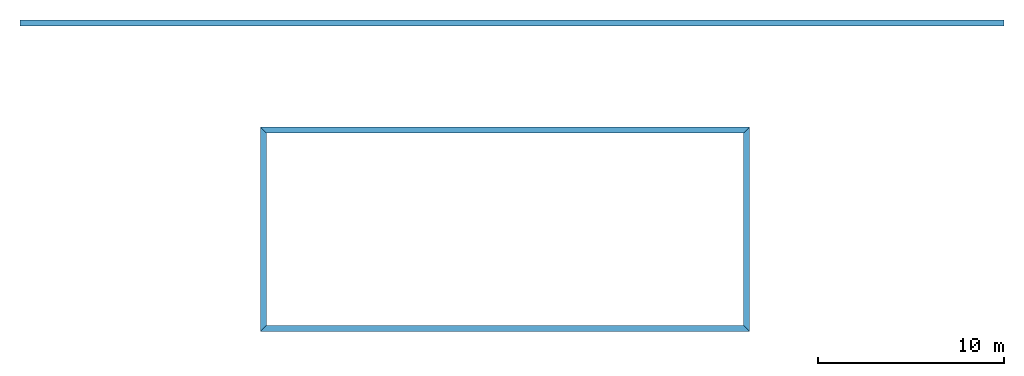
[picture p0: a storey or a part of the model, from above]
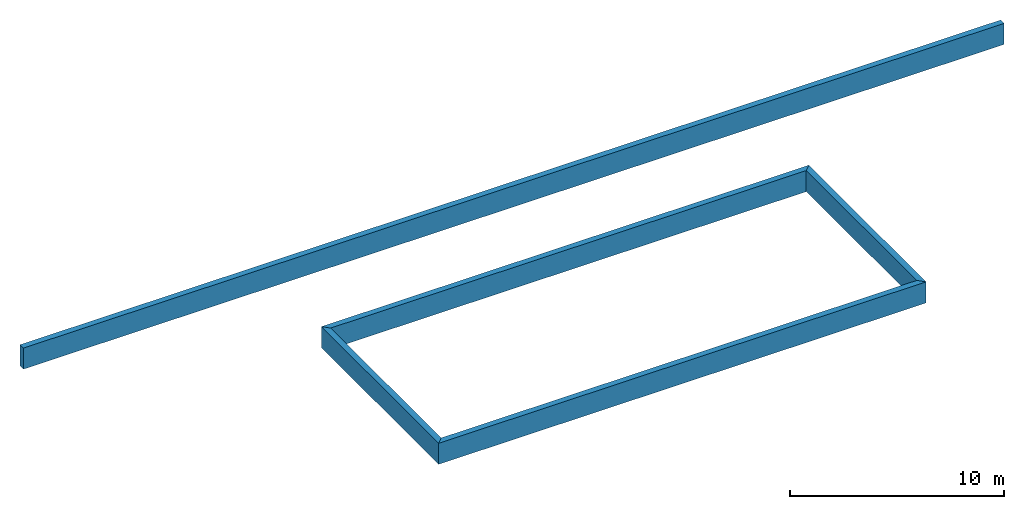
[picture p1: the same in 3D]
Properties of the parts of a building model (IFC2X3), part 1 of 2

# File
Description: ViewDefinition [CoordinationView_V2.0], Option [Elements to export: Visible elements (on all stories)], Option [Partial Structure Display: Entire Model], Option [IFC Domain: All], Option [Structural Function: All Elements], Option [Convert Grid elements: On], Option [Convert IFC Annotations and Archicad 2D elements: Off], Option [Convert 2D symbols of Doors and Windows: Off], Option [Export geometries that Participates in Collision Detection only: Off], Option [Split complex elements: Off], Option [Material Preservation: Explode where necessary], Option [Elements in Solid Element Operations: Extruded/revolved], Option [Elements with junctions: Extruded/revolved without junctions], Option [IFC Model position: Survey Point and Project Origin], Option [Curtain Wall export mode: Container Element], Option [Railing export mode: Single Element], Option [Stair export mode: Container Element], Option [Properties To Export: All properties], Option [Space containment: Off], Option [Geometry to type objects: Off], Option [Element Properties: All], Option [Building Material Properties: Off], Option [Element Parameters: Off], Option [Component Parameters: Off], Option [IFC Base Quantities: Off], Option [Door Window Parameters: On], Option [IFC Space boundaries: Off], Option [Archicad Zone Categories as IFC Space classification data: Off], Option [Element Classifications: On]
File name: \\Mac\Dropbox\PROJECTES\PROJECTES ACTIUS\1791- CR-BQ FA3\ENTREGUES\CR_BLOC FASE 3_01_05\EDITABLES\DOC GRÀFICA\CR-BLOC FASE 3_v4.ifc
Time: 2026-05-06T10:31:25
Author: Architect
Organization: Building Designer Office
Written by: DDS_IFC v3.0
Made in: Graphisoft - Archicad - 29.0.0
Authorization: The authorising person

# IfcSite, Sitio
RefLatitude: 47, 33, 34, 948800; RefLongitude: 19, 3, 17, 204400; RefElevation: 0 mm

# IfcBuildingStorey (4)
In: Construcción
Name | Elevation (mm)
PLANTA 3 | 7300
PLANTA 1ª | 0
PLANTA 2ª | 3650
-1. Piso | -3650

# IfcBuildingElementProxy: ARQ_GN002_Generic Estructural 250 x 345 (6)
Material: ARQ_GN002_Generic Estructural
AC_Pset_RenovationAndPhasing - Renovation Status: Existing
Name | In
2 x CRE - 005 | -1. Piso
2 x CRE - 005 | PLANTA 1ª
2 x CRE - 005 | PLANTA 2ª

# IfcBuildingElementProxy: ARQ_GN002_Generic Estructural 350 x 299 (3)
Material: ARQ_GN002_Generic Estructural
AC_Pset_RenovationAndPhasing - Renovation Status: Existing
Name | In
CRE - 005 | -1. Piso
CRE - 005 | PLANTA 1ª
CRE - 005 | PLANTA 2ª

# IfcBuildingElementProxy: ARQ_GN002_Generic Estructural 350 x 360 (3)
Material: ARQ_GN002_Generic Estructural
AC_Pset_RenovationAndPhasing - Renovation Status: Existing
Name | In
CRE - 005 | -1. Piso
CRE - 005 | PLANTA 1ª
CRE - 005 | PLANTA 2ª

# IfcBuildingElementProxy: ARQ_GN002_Generic Estructural 350 x 400 (3)
Material: ARQ_GN002_Generic Estructural
AC_Pset_RenovationAndPhasing - Renovation Status: Existing
Name | In
CRE - 005 | -1. Piso
CRE - 005 | PLANTA 1ª
CRE - 005 | PLANTA 2ª

# IfcBuildingElementProxy: ARQ_GN002_Generic Estructural 350 x 445 (2)
Material: ARQ_GN002_Generic Estructural
AC_Pset_RenovationAndPhasing - Renovation Status: Existing
Name | In
CRE - 005 | -1. Piso
CRE - 005 | PLANTA 1ª

# IfcBuildingElementProxy: ARQ_GN002_Generic Estructural 350 x 450 (39)
Material: ARQ_GN002_Generic Estructural
AC_Pset_RenovationAndPhasing - Renovation Status: Existing
Name | In
14 x CRE - 005 | -1. Piso
13 x CRE - 005 | PLANTA 1ª
12 x CRE - 005 | PLANTA 2ª

# IfcBuildingElementProxy: ARQ_GN002_Generic Estructural 350 x 515 (2)
In: PLANTA 2ª
Material: ARQ_GN002_Generic Estructural
AC_Pset_RenovationAndPhasing - Renovation Status: Existing

# IfcBuildingElementProxy: ARQ_GN002_Generic Estructural 350 x 605, CRE - 005
In: PLANTA 2ª
Material: ARQ_GN002_Generic Estructural
AC_Pset_RenovationAndPhasing - Renovation Status: Existing

# IfcBuildingElementProxy: ARQ_GN002_Generic Estructural 353 x 445 (3)
Material: ARQ_GN002_Generic Estructural
AC_Pset_RenovationAndPhasing - Renovation Status: Existing
Name | In
CRE - 005 | -1. Piso
CRE - 005 | PLANTA 1ª
CRE - 005 | PLANTA 2ª

# IfcBuildingElementProxy: ARQ_GN002_Generic Estructural 353 x 450 (3)
Material: ARQ_GN002_Generic Estructural
AC_Pset_RenovationAndPhasing - Renovation Status: Existing
Name | In
CRE - 005 | -1. Piso
CRE - 005 | PLANTA 1ª
CRE - 005 | PLANTA 2ª

# IfcBuildingElementProxy: ARQ_GN002_Generic Estructural 353 x 451, CRE - 005
In: PLANTA 2ª
Material: ARQ_GN002_Generic Estructural
AC_Pset_RenovationAndPhasing - Renovation Status: Existing

# IfcBuildingElementProxy: ARQ_GN002_Generic Estructural 400 x 400 (20)
Material: ARQ_GN002_Generic Estructural
AC_Pset_RenovationAndPhasing - Renovation Status: Existing
Name | In
7 x CRE - 005 | -1. Piso
8 x CRE - 005 | PLANTA 1ª
5 x CRE - 005 | PLANTA 2ª

# IfcBuildingElementProxy: ARQ_GN002_Generic Estructural 400 x 405 (28)
Material: ARQ_GN002_Generic Estructural
AC_Pset_RenovationAndPhasing - Renovation Status: Existing
Name | In
8 x CRE - 005 | -1. Piso
7 x CRE - 005 | PLANTA 1ª
13 x CRE - 005 | PLANTA 2ª

# IfcBuildingElementProxy: ARQ_GN002_Generic Estructural 400 x 552, CRE - 005
In: PLANTA 2ª
Material: ARQ_GN002_Generic Estructural
AC_Pset_RenovationAndPhasing - Renovation Status: Existing

# IfcBuildingElementProxy: ARQ_GN002_Generic Estructural 400 x 555, CRE - 005
In: PLANTA 2ª
Material: ARQ_GN002_Generic Estructural
AC_Pset_RenovationAndPhasing - Renovation Status: Existing

# IfcBuildingElementProxy: ARQ_GN002_Generic Estructural 410 x 400 (3)
Material: ARQ_GN002_Generic Estructural
AC_Pset_RenovationAndPhasing - Renovation Status: Existing
Name | In
CRE - 005 | -1. Piso
CRE - 005 | PLANTA 1ª
CRE - 005 | PLANTA 2ª

# IfcBuildingElementProxy: ARQ_GN002_Generic Estructural 451 x 320 (3)
Material: ARQ_GN002_Generic Estructural
AC_Pset_RenovationAndPhasing - Renovation Status: Existing
Name | In
CRE - 005 | -1. Piso
CRE - 005 | PLANTA 1ª
CRE - 005 | PLANTA 2ª

# IfcBuildingElementProxy: ARQ_GN002_Generic Estructural 513 x 445 (3)
Material: ARQ_GN002_Generic Estructural
AC_Pset_RenovationAndPhasing - Renovation Status: Existing
Name | In
CRE - 005 | -1. Piso
CRE - 005 | PLANTA 1ª
CRE - 005 | PLANTA 2ª

# IfcBuildingElementProxy: ARQ_GN002_Generic Estructural 562 x 445 (2)
Material: ARQ_GN002_Generic Estructural
AC_Pset_RenovationAndPhasing - Renovation Status: Existing
Name | In
CRE - 005 | -1. Piso
CRE - 005 | PLANTA 1ª

# IfcBuildingElementProxy: ARQ_GN002_Generic Estructural 562 x 605, CRE - 005
In: PLANTA 2ª
Material: ARQ_GN002_Generic Estructural
AC_Pset_RenovationAndPhasing - Renovation Status: Existing

# IfcBuildingElementProxy: Puerta 27 (28)
Name | In | Renovation Status
PF-07D | PLANTA 1ª | Existing
PF-08D | PLANTA 1ª | Existing
PF-04D | PLANTA 1ª | Existing
PF-05D | PLANTA 1ª | Existing
PF-06D | PLANTA 1ª | Existing
PF-10D | PLANTA 1ª | Existing
PF-09D | PLANTA 1ª | Existing
3 x P-02 | PLANTA 1ª | New
P-03 | PLANTA 1ª | New
PM-3 | PLANTA 1ª | New
PF-04D | PLANTA 2ª | Existing
2 x PF-05D | PLANTA 2ª | Existing
PF-06D | PLANTA 2ª | Existing
PF-19D | PLANTA 2ª | Existing
PF-23D | PLANTA 2ª | Existing
PF-26D | PLANTA 2ª | Existing
PF-25D | PLANTA 2ª | Existing
PF-20D | PLANTA 2ª | Existing
PF-22D | PLANTA 2ª | Existing
PF-24D | PLANTA 2ª | Existing
PF-21D | PLANTA 2ª | Existing
PF-18D | PLANTA 2ª | Existing
P-03 | PLANTA 2ª | New
P-02 | PLANTA 2ª | New
PM-3 | PLANTA 2ª | New

# IfcBuildingElementProxy: Puerta Corredera Empotrada 27 (19)
Name | In | Renovation Status
6 x P-01 | PLANTA 1ª | New
3 x P-04 | PLANTA 1ª | New
5 x PF-14D | PLANTA 2ª | Existing
3 x P-04 | PLANTA 2ª | New
2 x P-01 | PLANTA 2ª | New

# IfcBuildingElementProxy: Puerta Corredera Exterior 27 (9)
Name | In | Renovation Status
PF-12D | PLANTA 1ª | Existing
P-05 | PLANTA 1ª | New
PM-2 | PLANTA 1ª | New
5 x PF-13D | PLANTA 2ª | Existing
P-05 | PLANTA 2ª | New

# IfcBuildingElementProxy: Puerta Doble 27 (8)
Name | In | Renovation Status
PM-4 | PLANTA 1ª | New
PF-15D | PLANTA 1ª | Existing
PM-4 | PLANTA 2ª | New
2 x PF-31D | PLANTA 2ª | Existing
2 x PF-32D | PLANTA 2ª | Existing
PF-30D | PLANTA 2ª | Existing

# IfcBuildingElementProxy: Puerta Entrada 27, PM-1
In: PLANTA 1ª
AC_Pset_RenovationAndPhasing - Renovation Status: New

# IfcBuildingElementProxy: Puerta Metal 27 (4)
AC_Pset_RenovationAndPhasing - Renovation Status: New
Name | In
P-02 | PLANTA 1ª
PF-1 | PLANTA 1ª
P-02 | PLANTA 2ª
PF-1 | PLANTA 2ª

# IfcBuildingElementProxy: Puerta Metal Doble 27 (2)
AC_Pset_RenovationAndPhasing - Renovation Status: New
Name | In
PF-2 | PLANTA 1ª
PF-2 | PLANTA 2ª

# IfcBuildingElementProxy: Puerta Rápida Enrrollable 27 (4)
AC_Pset_RenovationAndPhasing - Renovation Status: New
Name | In
2 x P- Transfer | PLANTA 1ª
2 x P- Transfer | PLANTA 2ª

# IfcBuildingElementProxy: Ventana 27 (4)
AC_Pset_RenovationAndPhasing - Renovation Status: New
Name | In
3 x F-02 | PLANTA 1ª
F-02 | PLANTA 2ª

# IfcBuildingElementProxy: Ventana Escaparate 27 (15)
Pset_ManufacturerOccurrence - SerialNumber: No
AC_Pset_RenovationAndPhasing - Renovation Status: New
Name | In
M-08 | PLANTA 1ª
M-09 | PLANTA 1ª
M-02 | PLANTA 1ª
M-01 | PLANTA 1ª
M-06 | PLANTA 1ª
M-07 | PLANTA 1ª
M-04 | PLANTA 1ª
M-03 | PLANTA 1ª
M-11 | PLANTA 1ª
M-05 | PLANTA 1ª
M-13 | PLANTA 2ª
M-14 | PLANTA 2ª
M-15 | PLANTA 2ª
M-12 | PLANTA 2ª
M-10 | PLANTA 1ª

# IfcBuildingElementProxy: Ventana Vertical Multi-Faja 27 (57)
Name | In | Renovation Status
17 x V - 008 | -1. Piso | Existing
12 x F01 | PLANTA 1ª | Existing
5 x V - 008 | PLANTA 1ª | Existing
V - 010 | PLANTA 1ª | Existing
V - 009 | PLANTA 1ª | Existing
F01 | PLANTA 1ª | New
9 x V - 008 | PLANTA 2ª | Existing
V - 013 | PLANTA 2ª | Existing
V - 012 | PLANTA 2ª | Existing
V - 011 | PLANTA 2ª | Existing
8 x F01 | PLANTA 2ª | Existing

# IfcCovering: ARQ_AM253_Tarkett IQ Clar 2 (9)
Classification: 40.20.20.20 Paviments (GuBIMclass CA); Material: ARQ_AM253_Tarkett IQ Clar
06-ESPAIS - 06-05-Superficie: 0 m2; 06-01-Tipus us general: .; 06-01-Tipus us especific: .; 06-02-Numero: 0; 06-03-Nom: .; 06-04-Nivell: .; 06-03-Alçada lliure: 0; 06-06-Ocupació: 0
04-DIMENSIONS - 04-03-Alçada-m: 2 mm; 04-04-Espesor-m: 2 mm; 04-06-Area-m2: 0 m2; 04-07-Volum-m3: 0; 04-08-Diametre-Exterior: 0; 04-09-Diametre-Interior: 0
AC_Pset_RenovationAndPhasing - Renovation Status: New
07-PROPIETATS GENERALS - 07-01-Acabat: HPL
05-MANTENIMENT - 05-01-Fabricant: .; 05-02-Marca: .; 05-03-Model: .; 05-06-Data installacio: aa/mm/dd; 05-07-Data inici garantia: aa/mm/dd; 05-08-Data final garantia: aa/mm/dd
03-PRETACIONS - 03-01-Material: .; 03-02-RF: 0; 03-03-Pes-Kg: 0; 03-04-Potencia-W: 0; 03-05-Voltatge-V: 0; 03-06-Cabal -l/s: 0
02-LOCALIZACIÓ - 02-01-Nivell localització: .; 02-02-Codi ubicacio: .
01-IDENTIFICADOR - 01-04-Tipus installacio: .; 01-05-Unitat de mesura: .
Pset_CoveringCommon - Material: ARQ_AM253_Tarkett IQ Clar; TotalThickness: 2 mm
Name | In | 04-05-Perímetre-m (m2) | 01-01-Nom tipus
SLA - 013 | PLANTA 1ª | 3.22825 | SLA - 013
SLA - 013 | PLANTA 1ª | 223.981 | SLA - 013
SLA - 014 | PLANTA 1ª | 3.20742 | SLA - 014
SLA - 013 | PLANTA 1ª | 26.1483 | SLA - 013
SLA - 013 | PLANTA 1ª | 13.7227 | SLA - 013
SLA - 013 | PLANTA 1ª | 6.23319 | SLA - 013
SLA - 013 | PLANTA 1ª | 3.23513 | SLA - 013
SLA - 013 | PLANTA 2ª | 0.0376921 | SLA - 013
SLA - 013 | PLANTA 2ª | 205.367 | SLA - 013

# IfcCovering: ARQ_AM253_Tarkett IQ Habitacions 2 (4)
Classification: 40.20.20.20 Paviments (GuBIMclass CA); Material: ARQ_AM253_Tarkett IQ Habitacions
Pset_CoveringCommon - Material: ARQ_AM253_Tarkett IQ Habitacions; TotalThickness: 2 mm
01-IDENTIFICADOR - 01-01-Nom tipus: SLA - 013; 01-04-Tipus installacio: .; 01-05-Unitat de mesura: .
02-LOCALIZACIÓ - 02-01-Nivell localització: .; 02-02-Codi ubicacio: .
03-PRETACIONS - 03-01-Material: .; 03-02-RF: 0; 03-03-Pes-Kg: 0; 03-04-Potencia-W: 0; 03-05-Voltatge-V: 0; 03-06-Cabal -l/s: 0
04-DIMENSIONS - 04-07-Volum-m3: 0; 04-08-Diametre-Exterior: 0; 04-09-Diametre-Interior: 0; 04-03-Alçada-m: 2 mm; 04-04-Espesor-m: 2 mm; 04-06-Area-m2: 0 m2
05-MANTENIMENT - 05-01-Fabricant: .; 05-02-Marca: .; 05-03-Model: .; 05-06-Data installacio: aa/mm/dd; 05-07-Data inici garantia: aa/mm/dd; 05-08-Data final garantia: aa/mm/dd
07-PROPIETATS GENERALS - 07-01-Acabat: HPL
AC_Pset_RenovationAndPhasing - Renovation Status: Existing
06-ESPAIS - 06-05-Superficie: 0 m2; 06-01-Tipus us general: .; 06-01-Tipus us especific: .; 06-02-Numero: 0; 06-03-Nom: .; 06-04-Nivell: .; 06-03-Alçada lliure: 0; 06-06-Ocupació: 0
Name | In | 04-05-Perímetre-m (m2)
SLA - 013 | PLANTA 1ª | 70.9887
SLA - 013 | PLANTA 1ª | 74.5234
SLA - 013 | PLANTA 2ª | 61.8411
SLA - 013 | PLANTA 2ª | 65.547

# IfcFurnishingElement: Armario Mural 2P 10 (4)
In: PLANTA 1ª
Classification: 60.20.30.70 Altres mobiliaris mòbils (GuBIMclass CA)
01-IDENTIFICADOR - 01-01-Nom tipus: 60.20.66 Armari; 01-04-Tipus installacio: .; 01-05-Unitat de mesura: .
03-PRETACIONS - 03-01-Material: .; 03-02-RF: 0; 03-03-Pes-Kg: 0; 03-04-Potencia-W: 0; 03-05-Voltatge-V: 0; 03-06-Cabal -l/s: 0
02-LOCALIZACIÓ - 02-01-Nivell localització: .; 02-02-Codi ubicacio: .
04-DIMENSIONS - 04-07-Volum-m3: 0; 04-08-Diametre-Exterior: 0; 04-09-Diametre-Interior: 0; 04-03-Alçada-m: 750 mm; 04-06-Area-m2: 0 m2
05-MANTENIMENT - 05-01-Fabricant: .; 05-02-Marca: .; 05-03-Model: .; 05-06-Data installacio: aa/mm/dd; 05-07-Data inici garantia: aa/mm/dd; 05-08-Data final garantia: aa/mm/dd
07-PROPIETATS GENERALS - 07-01-Acabat: HPL
06-ESPAIS - 06-01-Tipus us general: .; 06-01-Tipus us especific: .; 06-02-Numero: 0; 06-03-Nom: .; 06-04-Nivell: .; 06-03-Alçada lliure: 0; 06-06-Ocupació: 0; 06-05-Superficie: 0 m2
AC_Pset_RenovationAndPhasing - Renovation Status: New
Name | 04-02-Amplada-m (mm) | 04-05-Perímetre-m (m2)
60.20.66 Armari | 299 | 4.13565
60.20.66 Armari | 300 | 5.83694
2 x 60.20.66 Armari | 300 | 4.19354

# IfcFurnishingElement: Armarios 27, 60.20.42 Armari
In: PLANTA 1ª
Classification: 60.20.30.70 Altres mobiliaris mòbils (GuBIMclass CA)
01-IDENTIFICADOR - 01-01-Nom tipus: 60.20.42 Armari; 01-04-Tipus installacio: .; 01-05-Unitat de mesura: .
02-LOCALIZACIÓ - 02-01-Nivell localització: .; 02-02-Codi ubicacio: .
03-PRETACIONS - 03-01-Material: .; 03-02-RF: 0; 03-03-Pes-Kg: 0; 03-04-Potencia-W: 0; 03-05-Voltatge-V: 0; 03-06-Cabal -l/s: 0
04-DIMENSIONS - 04-07-Volum-m3: 0; 04-08-Diametre-Exterior: 0; 04-09-Diametre-Interior: 0; 04-02-Amplada-m: 299.523 mm; 04-03-Alçada-m: 2000 mm; 04-05-Perímetre-m: 42.3208 m2; 04-06-Area-m2: 0 m2
05-MANTENIMENT - 05-01-Fabricant: .; 05-02-Marca: .; 05-03-Model: .; 05-06-Data installacio: aa/mm/dd; 05-07-Data inici garantia: aa/mm/dd; 05-08-Data final garantia: aa/mm/dd
06-ESPAIS - 06-01-Tipus us general: .; 06-01-Tipus us especific: .; 06-02-Numero: 0; 06-03-Nom: .; 06-04-Nivell: .; 06-03-Alçada lliure: 0; 06-06-Ocupació: 0; 06-05-Superficie: 0 m2
07-PROPIETATS GENERALS - 07-01-Acabat: HPL
AC_Pset_RenovationAndPhasing - Renovation Status: New

# IfcFurnishingElement: Cama Hospital 27 (12)
Classification: 60.20.30.50 Llits (GuBIMclass CA)
01-IDENTIFICADOR - 01-04-Tipus installacio: .; 01-05-Unitat de mesura: .
03-PRETACIONS - 03-01-Material: .; 03-02-RF: 0; 03-03-Pes-Kg: 0; 03-04-Potencia-W: 0; 03-05-Voltatge-V: 0; 03-06-Cabal -l/s: 0
02-LOCALIZACIÓ - 02-01-Nivell localització: .; 02-02-Codi ubicacio: .
04-DIMENSIONS - 04-07-Volum-m3: 0; 04-08-Diametre-Exterior: 0; 04-09-Diametre-Interior: 0; 04-02-Amplada-m: 2000 mm; 04-05-Perímetre-m: 9.78223 m2; 04-06-Area-m2: 0 m2
06-ESPAIS - 06-01-Tipus us general: .; 06-01-Tipus us especific: .; 06-02-Numero: 0; 06-03-Nom: .; 06-04-Nivell: .; 06-03-Alçada lliure: 0; 06-06-Ocupació: 0; 06-05-Superficie: 0 m2
07-PROPIETATS GENERALS - 07-01-Acabat: HPL
05-MANTENIMENT - 05-01-Fabricant: .; 05-02-Marca: .; 05-03-Model: .; 05-06-Data installacio: aa/mm/dd; 05-07-Data inici garantia: aa/mm/dd; 05-08-Data final garantia: aa/mm/dd
AC_Pset_RenovationAndPhasing - Renovation Status: New
Name | In | 01-01-Nom tipus | 04-03-Alçada-m (mm)
60.20.35 Armari | PLANTA 1ª | 60.20.35 Armari | 1000
5 x 60.20.35 Armari | PLANTA 1ª | 60.20.35 Armari | 600
3 x 60.20.44 Armari | PLANTA 1ª | 60.20.44 Armari | 600
2 x 60.20.44 Armari | PLANTA 2ª | 60.20.44 Armari | 600
60.20.44 Armari | PLANTA 2ª | 60.20.44 Armari | 1000

# IfcFurnishingElement: Escritorio 27, 60.20.51 Armari
In: PLANTA 1ª
Classification: 60.20.30 Mobiliari mòbil (GuBIMclass CA)
02-LOCALIZACIÓ - 02-01-Nivell localització: .; 02-02-Codi ubicacio: .
01-IDENTIFICADOR - 01-01-Nom tipus: 60.20.51 Armari; 01-04-Tipus installacio: .; 01-05-Unitat de mesura: .
04-DIMENSIONS - 04-07-Volum-m3: 0; 04-08-Diametre-Exterior: 0; 04-09-Diametre-Interior: 0; 04-02-Amplada-m: 700.128 mm; 04-03-Alçada-m: 720 mm; 04-05-Perímetre-m: 6.23012 m2; 04-06-Area-m2: 0 m2
03-PRETACIONS - 03-01-Material: .; 03-02-RF: 0; 03-03-Pes-Kg: 0; 03-04-Potencia-W: 0; 03-05-Voltatge-V: 0; 03-06-Cabal -l/s: 0
05-MANTENIMENT - 05-01-Fabricant: .; 05-02-Marca: .; 05-03-Model: .; 05-06-Data installacio: aa/mm/dd; 05-07-Data inici garantia: aa/mm/dd; 05-08-Data final garantia: aa/mm/dd
07-PROPIETATS GENERALS - 07-01-Acabat: HPL
06-ESPAIS - 06-01-Tipus us general: .; 06-01-Tipus us especific: .; 06-02-Numero: 0; 06-03-Nom: .; 06-04-Nivell: .; 06-03-Alçada lliure: 0; 06-06-Ocupació: 0; 06-05-Superficie: 0 m2
AC_Pset_RenovationAndPhasing - Renovation Status: New

# IfcFurnishingElement: Kit Ducha 27, 60.20.42 Armari
In: PLANTA 1ª
Classification: 60.20.30.70 Altres mobiliaris mòbils (GuBIMclass CA)
04-DIMENSIONS - 04-02-Amplada-m: 1000 mm; 04-03-Alçada-m: 115 mm; 04-05-Perímetre-m: 0.331595 m2; 04-06-Area-m2: 0 m2; 04-07-Volum-m3: 0; 04-08-Diametre-Exterior: 0; 04-09-Diametre-Interior: 0
AC_Pset_RenovationAndPhasing - Renovation Status: New
07-PROPIETATS GENERALS - 07-01-Acabat: HPL
06-ESPAIS - 06-01-Tipus us general: .; 06-01-Tipus us especific: .; 06-02-Numero: 0; 06-03-Nom: .; 06-04-Nivell: .; 06-03-Alçada lliure: 0; 06-06-Ocupació: 0; 06-05-Superficie: 0 m2
05-MANTENIMENT - 05-01-Fabricant: .; 05-02-Marca: .; 05-03-Model: .; 05-06-Data installacio: aa/mm/dd; 05-07-Data inici garantia: aa/mm/dd; 05-08-Data final garantia: aa/mm/dd
03-PRETACIONS - 03-01-Material: .; 03-02-RF: 0; 03-03-Pes-Kg: 0; 03-04-Potencia-W: 0; 03-05-Voltatge-V: 0; 03-06-Cabal -l/s: 0
02-LOCALIZACIÓ - 02-01-Nivell localització: .; 02-02-Codi ubicacio: .
01-IDENTIFICADOR - 01-01-Nom tipus: 60.20.42 Armari; 01-04-Tipus installacio: .; 01-05-Unitat de mesura: .

# IfcFurnishingElement: MacBook 27 (12)
Classification: 60.20.30.70 Altres mobiliaris mòbils (GuBIMclass CA)
01-IDENTIFICADOR - 01-01-Nom tipus: 60.20.37 Armari; 01-04-Tipus installacio: .; 01-05-Unitat de mesura: .
02-LOCALIZACIÓ - 02-01-Nivell localització: .; 02-02-Codi ubicacio: .
04-DIMENSIONS - 04-07-Volum-m3: 0; 04-08-Diametre-Exterior: 0; 04-09-Diametre-Interior: 0; 04-02-Amplada-m: 266.954 mm; 04-03-Alçada-m: 24.892 mm; 04-05-Perímetre-m: 0.756901 m2; 04-06-Area-m2: 0 m2
03-PRETACIONS - 03-01-Material: .; 03-02-RF: 0; 03-03-Pes-Kg: 0; 03-04-Potencia-W: 0; 03-05-Voltatge-V: 0; 03-06-Cabal -l/s: 0
05-MANTENIMENT - 05-01-Fabricant: .; 05-02-Marca: .; 05-03-Model: .; 05-06-Data installacio: aa/mm/dd; 05-07-Data inici garantia: aa/mm/dd; 05-08-Data final garantia: aa/mm/dd
06-ESPAIS - 06-01-Tipus us general: .; 06-01-Tipus us especific: .; 06-02-Numero: 0; 06-03-Nom: .; 06-04-Nivell: .; 06-03-Alçada lliure: 0; 06-06-Ocupació: 0; 06-05-Superficie: 0 m2
AC_Pset_RenovationAndPhasing - Renovation Status: New
07-PROPIETATS GENERALS - 07-01-Acabat: HPL
Name | In
6 x 60.20.37 Armari | PLANTA 1ª
6 x 60.20.37 Armari | PLANTA 2ª

# IfcFurnishingElement: Mesa Oficina Rect 27 (6)
Classification: 60.20.30.70 Altres mobiliaris mòbils (GuBIMclass CA)
01-IDENTIFICADOR - 01-01-Nom tipus: 60.20.51 Armari; 01-04-Tipus installacio: .; 01-05-Unitat de mesura: .
02-LOCALIZACIÓ - 02-01-Nivell localització: .; 02-02-Codi ubicacio: .
03-PRETACIONS - 03-01-Material: .; 03-02-RF: 0; 03-03-Pes-Kg: 0; 03-04-Potencia-W: 0; 03-05-Voltatge-V: 0; 03-06-Cabal -l/s: 0
04-DIMENSIONS - 04-07-Volum-m3: 0; 04-08-Diametre-Exterior: 0; 04-09-Diametre-Interior: 0; 04-03-Alçada-m: 750 mm; 04-06-Area-m2: 0 m2
05-MANTENIMENT - 05-01-Fabricant: .; 05-02-Marca: .; 05-03-Model: .; 05-06-Data installacio: aa/mm/dd; 05-07-Data inici garantia: aa/mm/dd; 05-08-Data final garantia: aa/mm/dd
06-ESPAIS - 06-01-Tipus us general: .; 06-01-Tipus us especific: .; 06-02-Numero: 0; 06-03-Nom: .; 06-04-Nivell: .; 06-03-Alçada lliure: 0; 06-06-Ocupació: 0; 06-05-Superficie: 0 m2
07-PROPIETATS GENERALS - 07-01-Acabat: HPL
AC_Pset_RenovationAndPhasing - Renovation Status: New
Name | In | 04-02-Amplada-m (mm) | 04-05-Perímetre-m (m2)
60.20.51 Armari | PLANTA 1ª | 750 | 12.2099
60.20.51 Armari | PLANTA 1ª | 850 | 16.4315
2 x 60.20.51 Armari | PLANTA 1ª | 650 | 2.13214
2 x 60.20.51 Armari | PLANTA 2ª | 650 | 2.13214

# IfcFurnishingElement: Módulo Base Doble Puerta 24 (3)
Classification: 60.20.30.70 Altres mobiliaris mòbils (GuBIMclass CA)
01-IDENTIFICADOR - 01-01-Nom tipus: 60.20.52 Armari; 01-04-Tipus installacio: .; 01-05-Unitat de mesura: .
02-LOCALIZACIÓ - 02-01-Nivell localització: .; 02-02-Codi ubicacio: .
04-DIMENSIONS - 04-07-Volum-m3: 0; 04-08-Diametre-Exterior: 0; 04-09-Diametre-Interior: 0; 04-02-Amplada-m: 600 mm; 04-03-Alçada-m: 900 mm; 04-06-Area-m2: 0 m2
03-PRETACIONS - 03-01-Material: .; 03-02-RF: 0; 03-03-Pes-Kg: 0; 03-04-Potencia-W: 0; 03-05-Voltatge-V: 0; 03-06-Cabal -l/s: 0
06-ESPAIS - 06-01-Tipus us general: .; 06-01-Tipus us especific: .; 06-02-Numero: 0; 06-03-Nom: .; 06-04-Nivell: .; 06-03-Alçada lliure: 0; 06-06-Ocupació: 0; 06-05-Superficie: 0 m2
07-PROPIETATS GENERALS - 07-01-Acabat: HPL
AC_Pset_RenovationAndPhasing - Renovation Status: New
05-MANTENIMENT - 05-01-Fabricant: .; 05-02-Marca: .; 05-03-Model: .; 05-06-Data installacio: aa/mm/dd; 05-07-Data inici garantia: aa/mm/dd; 05-08-Data final garantia: aa/mm/dd
Name | In | 04-05-Perímetre-m (m2)
60.20.52 Armari | PLANTA 1ª | 11.6875
60.20.52 Armari | PLANTA 2ª | 7.90483
60.20.52 Armari | PLANTA 2ª | 11.6875

# IfcFurnishingElement: Nevera 27 (8)
Classification: 60.20.30.70 Altres mobiliaris mòbils (GuBIMclass CA)
01-IDENTIFICADOR - 01-01-Nom tipus: 60.20.53 Armari; 01-04-Tipus installacio: .; 01-05-Unitat de mesura: .
02-LOCALIZACIÓ - 02-01-Nivell localització: .; 02-02-Codi ubicacio: .
03-PRETACIONS - 03-01-Material: .; 03-02-RF: 0; 03-03-Pes-Kg: 0; 03-04-Potencia-W: 0; 03-05-Voltatge-V: 0; 03-06-Cabal -l/s: 0
04-DIMENSIONS - 04-07-Volum-m3: 0; 04-08-Diametre-Exterior: 0; 04-09-Diametre-Interior: 0; 04-03-Alçada-m: 1800 mm; 04-06-Area-m2: 0 m2
05-MANTENIMENT - 05-01-Fabricant: .; 05-02-Marca: .; 05-03-Model: .; 05-06-Data installacio: aa/mm/dd; 05-07-Data inici garantia: aa/mm/dd; 05-08-Data final garantia: aa/mm/dd
06-ESPAIS - 06-01-Tipus us general: .; 06-01-Tipus us especific: .; 06-02-Numero: 0; 06-03-Nom: .; 06-04-Nivell: .; 06-03-Alçada lliure: 0; 06-06-Ocupació: 0; 06-05-Superficie: 0 m2
07-PROPIETATS GENERALS - 07-01-Acabat: HPL
AC_Pset_RenovationAndPhasing - Renovation Status: New
Name | In | 04-02-Amplada-m (mm) | 04-05-Perímetre-m (m2)
60.20.53 Armari | PLANTA 1ª | 600 | 7.96279
3 x 60.20.53 Armari | PLANTA 1ª | 654.833 | 9.27421
3 x 60.20.53 Armari | PLANTA 2ª | 654.833 | 9.27421
60.20.53 Armari | PLANTA 2ª | 600 | 7.96279

# IfcFurnishingElement: Silla Oficina 01 10, 60.20.54 Armari
In: PLANTA 1ª
Classification: 60.20.30.70 Altres mobiliaris mòbils (GuBIMclass CA)
01-IDENTIFICADOR - 01-01-Nom tipus: 60.20.54 Armari; 01-04-Tipus installacio: .; 01-05-Unitat de mesura: .
02-LOCALIZACIÓ - 02-01-Nivell localització: .; 02-02-Codi ubicacio: .
03-PRETACIONS - 03-01-Material: .; 03-02-RF: 0; 03-03-Pes-Kg: 0; 03-04-Potencia-W: 0; 03-05-Voltatge-V: 0; 03-06-Cabal -l/s: 0
04-DIMENSIONS - 04-07-Volum-m3: 0; 04-08-Diametre-Exterior: 0; 04-09-Diametre-Interior: 0; 04-02-Amplada-m: 816.951 mm; 04-03-Alçada-m: 1000 mm; 04-05-Perímetre-m: 2.48725 m2; 04-06-Area-m2: 0 m2
06-ESPAIS - 06-01-Tipus us general: .; 06-01-Tipus us especific: .; 06-02-Numero: 0; 06-03-Nom: .; 06-04-Nivell: .; 06-03-Alçada lliure: 0; 06-06-Ocupació: 0; 06-05-Superficie: 0 m2
07-PROPIETATS GENERALS - 07-01-Acabat: HPL
AC_Pset_RenovationAndPhasing - Renovation Status: New
05-MANTENIMENT - 05-01-Fabricant: .; 05-02-Marca: .; 05-03-Model: .; 05-06-Data installacio: aa/mm/dd; 05-07-Data inici garantia: aa/mm/dd; 05-08-Data final garantia: aa/mm/dd

# IfcFurnishingElement: Silla Oficina 04 27 (18)
Classification: 60.20.30.70 Altres mobiliaris mòbils (GuBIMclass CA)
01-IDENTIFICADOR - 01-01-Nom tipus: 60.20.56 Armari; 01-04-Tipus installacio: .; 01-05-Unitat de mesura: .
03-PRETACIONS - 03-01-Material: .; 03-02-RF: 0; 03-03-Pes-Kg: 0; 03-04-Potencia-W: 0; 03-05-Voltatge-V: 0; 03-06-Cabal -l/s: 0
04-DIMENSIONS - 04-07-Volum-m3: 0; 04-08-Diametre-Exterior: 0; 04-09-Diametre-Interior: 0; 04-02-Amplada-m: 589.529 mm; 04-03-Alçada-m: 950 mm; 04-05-Perímetre-m: 2.16835 m2; 04-06-Area-m2: 0 m2
05-MANTENIMENT - 05-01-Fabricant: .; 05-02-Marca: .; 05-03-Model: .; 05-06-Data installacio: aa/mm/dd; 05-07-Data inici garantia: aa/mm/dd; 05-08-Data final garantia: aa/mm/dd
06-ESPAIS - 06-01-Tipus us general: .; 06-01-Tipus us especific: .; 06-02-Numero: 0; 06-03-Nom: .; 06-04-Nivell: .; 06-03-Alçada lliure: 0; 06-06-Ocupació: 0; 06-05-Superficie: 0 m2
02-LOCALIZACIÓ - 02-01-Nivell localització: .; 02-02-Codi ubicacio: .
07-PROPIETATS GENERALS - 07-01-Acabat: HPL
AC_Pset_RenovationAndPhasing - Renovation Status: New
Name | In
12 x 60.20.56 Armari | PLANTA 1ª
6 x 60.20.56 Armari | PLANTA 2ª

# IfcFurnishingElement: Teclado (Apple) 27 (5)
In: PLANTA 1ª
Classification: 60.20.30.70 Altres mobiliaris mòbils (GuBIMclass CA)
01-IDENTIFICADOR - 01-01-Nom tipus: 60.20.36 Armari; 01-04-Tipus installacio: .; 01-05-Unitat de mesura: .
02-LOCALIZACIÓ - 02-01-Nivell localització: .; 02-02-Codi ubicacio: .
03-PRETACIONS - 03-01-Material: .; 03-02-RF: 0; 03-03-Pes-Kg: 0; 03-04-Potencia-W: 0; 03-05-Voltatge-V: 0; 03-06-Cabal -l/s: 0
04-DIMENSIONS - 04-07-Volum-m3: 0; 04-08-Diametre-Exterior: 0; 04-09-Diametre-Interior: 0; 04-02-Amplada-m: 114 mm; 04-03-Alçada-m: 17 mm; 04-05-Perímetre-m: 0.295918 m2; 04-06-Area-m2: 0 m2
05-MANTENIMENT - 05-01-Fabricant: .; 05-02-Marca: .; 05-03-Model: .; 05-06-Data installacio: aa/mm/dd; 05-07-Data inici garantia: aa/mm/dd; 05-08-Data final garantia: aa/mm/dd
07-PROPIETATS GENERALS - 07-01-Acabat: HPL
06-ESPAIS - 06-01-Tipus us general: .; 06-01-Tipus us especific: .; 06-02-Numero: 0; 06-03-Nom: .; 06-04-Nivell: .; 06-03-Alçada lliure: 0; 06-06-Ocupació: 0; 06-05-Superficie: 0 m2
AC_Pset_RenovationAndPhasing - Renovation Status: New

# IfcFurnishingElement: WC Discapacitados 27, 60.20.40 Armari
In: PLANTA 1ª
Classification: 60.20.30.70 Altres mobiliaris mòbils (GuBIMclass CA)
01-IDENTIFICADOR - 01-01-Nom tipus: 60.20.40 Armari; 01-04-Tipus installacio: .; 01-05-Unitat de mesura: .
02-LOCALIZACIÓ - 02-01-Nivell localització: .; 02-02-Codi ubicacio: .
04-DIMENSIONS - 04-07-Volum-m3: 0; 04-08-Diametre-Exterior: 0; 04-09-Diametre-Interior: 0; 04-02-Amplada-m: 560 mm; 04-03-Alçada-m: 330 mm; 04-05-Perímetre-m: 2.06877 m2; 04-06-Area-m2: 0 m2
03-PRETACIONS - 03-01-Material: .; 03-02-RF: 0; 03-03-Pes-Kg: 0; 03-04-Potencia-W: 0; 03-05-Voltatge-V: 0; 03-06-Cabal -l/s: 0
05-MANTENIMENT - 05-01-Fabricant: .; 05-02-Marca: .; 05-03-Model: .; 05-06-Data installacio: aa/mm/dd; 05-07-Data inici garantia: aa/mm/dd; 05-08-Data final garantia: aa/mm/dd
06-ESPAIS - 06-01-Tipus us general: .; 06-01-Tipus us especific: .; 06-02-Numero: 0; 06-03-Nom: .; 06-04-Nivell: .; 06-03-Alçada lliure: 0; 06-06-Ocupació: 0; 06-05-Superficie: 0 m2
07-PROPIETATS GENERALS - 07-01-Acabat: HPL
AC_Pset_RenovationAndPhasing - Renovation Status: New

# IfcFurnishingElement: iMac 27 (5)
In: PLANTA 1ª
Classification: 60.20.30.70 Altres mobiliaris mòbils (GuBIMclass CA)
01-IDENTIFICADOR - 01-01-Nom tipus: 60.20.35 Armari; 01-04-Tipus installacio: .; 01-05-Unitat de mesura: .
02-LOCALIZACIÓ - 02-01-Nivell localització: .; 02-02-Codi ubicacio: .
03-PRETACIONS - 03-01-Material: .; 03-02-RF: 0; 03-03-Pes-Kg: 0; 03-04-Potencia-W: 0; 03-05-Voltatge-V: 0; 03-06-Cabal -l/s: 0
04-DIMENSIONS - 04-07-Volum-m3: 0; 04-08-Diametre-Exterior: 0; 04-09-Diametre-Interior: 0; 04-02-Amplada-m: 188.468 mm; 04-03-Alçada-m: 450.85 mm; 04-05-Perímetre-m: 1.23018 m2; 04-06-Area-m2: 0 m2
05-MANTENIMENT - 05-01-Fabricant: .; 05-02-Marca: .; 05-03-Model: .; 05-06-Data installacio: aa/mm/dd; 05-07-Data inici garantia: aa/mm/dd; 05-08-Data final garantia: aa/mm/dd
07-PROPIETATS GENERALS - 07-01-Acabat: HPL
06-ESPAIS - 06-01-Tipus us general: .; 06-01-Tipus us especific: .; 06-02-Numero: 0; 06-03-Nom: .; 06-04-Nivell: .; 06-03-Alçada lliure: 0; 06-06-Ocupació: 0; 06-05-Superficie: 0 m2
AC_Pset_RenovationAndPhasing - Renovation Status: New

# IfcSlab: ARQ_CE217_Armstrong 60x60 50 (683)
Classification: 40.20.10.10 Falsos sostres interiors (GuBIMclass CA); Material: ARQ_CE217_Armstrong 60x60 50 mm
01-IDENTIFICADOR - 01-01-Nom tipus: SLA - 026; 01-04-Tipus installacio: .; 01-05-Unitat de mesura: .
03-PRETACIONS - 03-01-Material: .; 03-02-RF: 0; 03-03-Pes-Kg: 0; 03-04-Potencia-W: 0; 03-05-Voltatge-V: 0; 03-06-Cabal -l/s: 0
02-LOCALIZACIÓ - 02-01-Nivell localització: .; 02-02-Codi ubicacio: .
04-DIMENSIONS - 04-07-Volum-m3: 0; 04-08-Diametre-Exterior: 0; 04-09-Diametre-Interior: 0; 04-03-Alçada-m: 50 mm; 04-04-Espesor-m: 50 mm; 04-05-Perímetre-m: 0.36 m2; 04-06-Area-m2: 0 m2
05-MANTENIMENT - 05-01-Fabricant: .; 05-02-Marca: .; 05-03-Model: .; 05-06-Data installacio: aa/mm/dd; 05-07-Data inici garantia: aa/mm/dd; 05-08-Data final garantia: aa/mm/dd
06-ESPAIS - 06-01-Tipus us general: .; 06-01-Tipus us especific: .; 06-02-Numero: 0; 06-03-Nom: .; 06-04-Nivell: .; 06-03-Alçada lliure: 0; 06-06-Ocupació: 0; 06-05-Superficie: 0 m2
07-PROPIETATS GENERALS - 07-01-Acabat: HPL
AC_Pset_RenovationAndPhasing - Renovation Status: New
Name | In
343 x SLA - 026 | PLANTA 1ª
340 x SLA - 026 | PLANTA 2ª

# IfcSlab: ARQ_CG063_Guix_Laminat_Hydro 53, SLA - 024
In: PLANTA 1ª
Classification: 40.20.10.10 Falsos sostres interiors (GuBIMclass CA); Material: ARQ_CG063_Guix_Laminat_Hydro 53 mm
01-IDENTIFICADOR - 01-01-Nom tipus: SLA - 024; 01-04-Tipus installacio: .; 01-05-Unitat de mesura: .
02-LOCALIZACIÓ - 02-01-Nivell localització: .; 02-02-Codi ubicacio: .
03-PRETACIONS - 03-01-Material: .; 03-02-RF: 0; 03-03-Pes-Kg: 0; 03-04-Potencia-W: 0; 03-05-Voltatge-V: 0; 03-06-Cabal -l/s: 0
04-DIMENSIONS - 04-07-Volum-m3: 0; 04-08-Diametre-Exterior: 0; 04-09-Diametre-Interior: 0; 04-03-Alçada-m: 53 mm; 04-04-Espesor-m: 53 mm; 04-05-Perímetre-m: 6.68541 m2; 04-06-Area-m2: 0 m2
05-MANTENIMENT - 05-01-Fabricant: .; 05-02-Marca: .; 05-03-Model: .; 05-06-Data installacio: aa/mm/dd; 05-07-Data inici garantia: aa/mm/dd; 05-08-Data final garantia: aa/mm/dd
06-ESPAIS - 06-01-Tipus us general: .; 06-01-Tipus us especific: .; 06-02-Numero: 0; 06-03-Nom: .; 06-04-Nivell: .; 06-03-Alçada lliure: 0; 06-06-Ocupació: 0; 06-05-Superficie: 0 m2
07-PROPIETATS GENERALS - 07-01-Acabat: HPL
AC_Pset_RenovationAndPhasing - Renovation Status: New

# IfcSlab: ARQ_CG064_CelRas_Guix_Continu 53 (25)
Classification: 40.20.10.10 Falsos sostres interiors (GuBIMclass CA); Material: ARQ_CG064_CelRas_Guix_Continu 53 mm
01-IDENTIFICADOR - 01-04-Tipus installacio: .; 01-05-Unitat de mesura: .
02-LOCALIZACIÓ - 02-01-Nivell localització: .; 02-02-Codi ubicacio: .
03-PRETACIONS - 03-01-Material: .; 03-02-RF: 0; 03-03-Pes-Kg: 0; 03-04-Potencia-W: 0; 03-05-Voltatge-V: 0; 03-06-Cabal -l/s: 0
04-DIMENSIONS - 04-07-Volum-m3: 0; 04-08-Diametre-Exterior: 0; 04-09-Diametre-Interior: 0; 04-03-Alçada-m: 53 mm; 04-04-Espesor-m: 53 mm; 04-06-Area-m2: 0 m2
05-MANTENIMENT - 05-01-Fabricant: .; 05-02-Marca: .; 05-03-Model: .; 05-06-Data installacio: aa/mm/dd; 05-07-Data inici garantia: aa/mm/dd; 05-08-Data final garantia: aa/mm/dd
06-ESPAIS - 06-01-Tipus us general: .; 06-01-Tipus us especific: .; 06-02-Numero: 0; 06-03-Nom: .; 06-04-Nivell: .; 06-03-Alçada lliure: 0; 06-06-Ocupació: 0; 06-05-Superficie: 0 m2
07-PROPIETATS GENERALS - 07-01-Acabat: HPL
Name | In | 01-01-Nom tipus | 04-05-Perímetre-m (m2) | Renovation Status
SLA - 013 | PLANTA 1ª | SLA - 013 | 3.20009 | New
SLA - 013 | PLANTA 1ª | SLA - 013 | 170.446 | New
SLA - 013 | PLANTA 1ª | SLA - 013 | 3.21337 | New
SLA - 014 | PLANTA 1ª | SLA - 014 | 3.20742 | New
SLA - 013 | PLANTA 1ª | SLA - 013 | 2.97426 | New
SLA - 013 | PLANTA 1ª | SLA - 013 | 8.29491 | New
SLA - 013 | PLANTA 1ª | SLA - 013 | 8.82576 | New
SLA - 013 | PLANTA 1ª | SLA - 013 | 12.1444 | New
SLA - 013 | PLANTA 1ª | SLA - 013 | 5.88755 | New
SLA - 013 | PLANTA 1ª | SLA - 013 | 6.24224 | New
SLA - 013 | PLANTA 1ª | SLA - 013 | 4.07903 | New
SLA - 014 | PLANTA 1ª | SLA - 014 | 13.0831 | Existing
SLA - 013 | PLANTA 2ª | SLA - 013 | 61.3766 | Existing
SLA - 015 | PLANTA 2ª | SLA - 015 | 38.878 | Existing
SLA - 014 | PLANTA 2ª | SLA - 014 | 4.09508 | Existing
SLA - 015 | PLANTA 2ª | SLA - 015 | 5.22992 | Existing
SLA - 016 | PLANTA 2ª | SLA - 016 | 5.40481 | Existing
SLA - 017 | PLANTA 2ª | SLA - 017 | 17.4141 | Existing
SLA - 017 | PLANTA 2ª | SLA - 017 | 11.0292 | Existing
SLA - 017 | PLANTA 2ª | SLA - 017 | 46.8142 | Existing
SLA - 013 | PLANTA 2ª | SLA - 013 | 9.47799 | Existing
SLA - 013 | PLANTA 2ª | SLA - 013 | 5.6967 | Existing
SLA - 017 | PLANTA 2ª | SLA - 017 | 17.3508 | Existing
SLA - 013 | PLANTA 2ª | SLA - 013 | 6.35941 | Existing
SLA - 014 | PLANTA 2ª | SLA - 014 | 16.1612 | Existing

# IfcSlab: ARQ_EN271_Camara_Aire 50, SLA - 026
In: PLANTA 1ª
Classification: 40.20.10.10 Falsos sostres interiors (GuBIMclass CA); Material: ARQ_EN271_Camara_Aire 50 mm
01-IDENTIFICADOR - 01-01-Nom tipus: SLA - 026; 01-04-Tipus installacio: .; 01-05-Unitat de mesura: .
03-PRETACIONS - 03-01-Material: .; 03-02-RF: 0; 03-03-Pes-Kg: 0; 03-04-Potencia-W: 0; 03-05-Voltatge-V: 0; 03-06-Cabal -l/s: 0
04-DIMENSIONS - 04-07-Volum-m3: 0; 04-08-Diametre-Exterior: 0; 04-09-Diametre-Interior: 0; 04-03-Alçada-m: 50 mm; 04-04-Espesor-m: 50 mm; 04-05-Perímetre-m: 0.36 m2; 04-06-Area-m2: 0 m2
05-MANTENIMENT - 05-01-Fabricant: .; 05-02-Marca: .; 05-03-Model: .; 05-06-Data installacio: aa/mm/dd; 05-07-Data inici garantia: aa/mm/dd; 05-08-Data final garantia: aa/mm/dd
06-ESPAIS - 06-01-Tipus us general: .; 06-01-Tipus us especific: .; 06-02-Numero: 0; 06-03-Nom: .; 06-04-Nivell: .; 06-03-Alçada lliure: 0; 06-06-Ocupació: 0; 06-05-Superficie: 0 m2
07-PROPIETATS GENERALS - 07-01-Acabat: HPL
AC_Pset_RenovationAndPhasing - Renovation Status: New
02-LOCALIZACIÓ - 02-01-Nivell localització: .; 02-02-Codi ubicacio: .

# IfcSlab: ARQ_FU091_HPL 30 (8)
Classification: 40.20.10.10 Falsos sostres interiors (GuBIMclass CA); Material: ARQ_FU091_HPL 30 mm
01-IDENTIFICADOR - 01-04-Tipus installacio: .; 01-05-Unitat de mesura: .
02-LOCALIZACIÓ - 02-01-Nivell localització: .; 02-02-Codi ubicacio: .
03-PRETACIONS - 03-01-Material: .; 03-02-RF: 0; 03-03-Pes-Kg: 0; 03-04-Potencia-W: 0; 03-05-Voltatge-V: 0; 03-06-Cabal -l/s: 0
05-MANTENIMENT - 05-01-Fabricant: .; 05-02-Marca: .; 05-03-Model: .; 05-06-Data installacio: aa/mm/dd; 05-07-Data inici garantia: aa/mm/dd; 05-08-Data final garantia: aa/mm/dd
06-ESPAIS - 06-01-Tipus us general: .; 06-01-Tipus us especific: .; 06-02-Numero: 0; 06-03-Nom: .; 06-04-Nivell: .; 06-03-Alçada lliure: 0; 06-06-Ocupació: 0; 06-05-Superficie: 0 m2
07-PROPIETATS GENERALS - 07-01-Acabat: HPL
04-DIMENSIONS - 04-07-Volum-m3: 0; 04-08-Diametre-Exterior: 0; 04-09-Diametre-Interior: 0; 04-03-Alçada-m: 30 mm; 04-04-Espesor-m: 30 mm; 04-06-Area-m2: 0 m2
AC_Pset_RenovationAndPhasing - Renovation Status: New
Name | In | 01-01-Nom tipus | 04-05-Perímetre-m (m2)
SLA - 029 | PLANTA 1ª | SLA - 029 | 1.30197
SLA - 029 | PLANTA 1ª | SLA - 029 | 1.809
SLA - 011 | PLANTA 2ª | SLA - 011 | 0.905187
SLA - 028 | PLANTA 2ª | SLA - 028 | 7.65293
SLA - 029 | PLANTA 2ª | SLA - 029 | 2.11627
SLA - 011 | PLANTA 2ª | SLA - 011 | 0.976729
SLA - 011 | PLANTA 2ª | SLA - 011 | 0.877291
SLA - 028 | PLANTA 2ª | SLA - 028 | 7.68622

# IfcSlab: ARQ_GN003_Generic tancaments interiors 30 (2)
In: PLANTA 1ª
Classification: 40.20.10.10 Falsos sostres interiors (GuBIMclass CA); Material: ARQ_GN003_Generic tancaments interiors 30 mm
01-IDENTIFICADOR - 01-04-Tipus installacio: .; 01-05-Unitat de mesura: .
03-PRETACIONS - 03-01-Material: .; 03-02-RF: 0; 03-03-Pes-Kg: 0; 03-04-Potencia-W: 0; 03-05-Voltatge-V: 0; 03-06-Cabal -l/s: 0
04-DIMENSIONS - 04-07-Volum-m3: 0; 04-08-Diametre-Exterior: 0; 04-09-Diametre-Interior: 0; 04-03-Alçada-m: 30 mm; 04-04-Espesor-m: 30 mm; 04-06-Area-m2: 0 m2
02-LOCALIZACIÓ - 02-01-Nivell localització: .; 02-02-Codi ubicacio: .
06-ESPAIS - 06-01-Tipus us general: .; 06-01-Tipus us especific: .; 06-02-Numero: 0; 06-03-Nom: .; 06-04-Nivell: .; 06-03-Alçada lliure: 0; 06-06-Ocupació: 0; 06-05-Superficie: 0 m2
05-MANTENIMENT - 05-01-Fabricant: .; 05-02-Marca: .; 05-03-Model: .; 05-06-Data installacio: aa/mm/dd; 05-07-Data inici garantia: aa/mm/dd; 05-08-Data final garantia: aa/mm/dd
07-PROPIETATS GENERALS - 07-01-Acabat: HPL
AC_Pset_RenovationAndPhasing - Renovation Status: New
Name | 01-01-Nom tipus | 04-05-Perímetre-m (m2)
SLA - 028 | SLA - 028 | 6.66623
SLA - 029 | SLA - 029 | 1.2715

# IfcSlab: ARQ_ME126_CelRas_Placa_Metallica 50 (500)
Classification: 40.20.10.10 Falsos sostres interiors (GuBIMclass CA); Material: ARQ_ME126_CelRas_Placa_Metallica 50 mm
01-IDENTIFICADOR - 01-01-Nom tipus: SLA - 026; 01-04-Tipus installacio: .; 01-05-Unitat de mesura: .
02-LOCALIZACIÓ - 02-01-Nivell localització: .; 02-02-Codi ubicacio: .
03-PRETACIONS - 03-01-Material: .; 03-02-RF: 0; 03-03-Pes-Kg: 0; 03-04-Potencia-W: 0; 03-05-Voltatge-V: 0; 03-06-Cabal -l/s: 0
04-DIMENSIONS - 04-07-Volum-m3: 0; 04-08-Diametre-Exterior: 0; 04-09-Diametre-Interior: 0; 04-03-Alçada-m: 50 mm; 04-04-Espesor-m: 50 mm; 04-06-Area-m2: 0 m2
05-MANTENIMENT - 05-01-Fabricant: .; 05-02-Marca: .; 05-03-Model: .; 05-06-Data installacio: aa/mm/dd; 05-07-Data inici garantia: aa/mm/dd; 05-08-Data final garantia: aa/mm/dd
06-ESPAIS - 06-01-Tipus us general: .; 06-01-Tipus us especific: .; 06-02-Numero: 0; 06-03-Nom: .; 06-04-Nivell: .; 06-03-Alçada lliure: 0; 06-06-Ocupació: 0; 06-05-Superficie: 0 m2
07-PROPIETATS GENERALS - 07-01-Acabat: HPL
AC_Pset_RenovationAndPhasing - Renovation Status: New
Name | In | 04-05-Perímetre-m (m2)
183 x SLA - 026 | PLANTA 1ª | 0.36
57 x SLA - 026 | PLANTA 1ª | 0.45
SLA - 026 | PLANTA 1ª | 0.240689
53 x SLA - 026 | PLANTA 2ª | 0.45
204 x SLA - 026 | PLANTA 2ª | 0.36
SLA - 026 | PLANTA 2ª | 0.359942
SLA - 026 | PLANTA 2ª | 0.276058

# IfcSlab: Armario Base 27 (7)
Type - PredefinedType: FLOOR
Classification: 70.50.10.30 Arbustives (GuBIMclass CA)
01-IDENTIFICADOR - 01-04-Tipus installacio: .; 01-05-Unitat de mesura: .
02-LOCALIZACIÓ - 02-01-Nivell localització: .; 02-02-Codi ubicacio: .
04-DIMENSIONS - 04-07-Volum-m3: 0; 04-08-Diametre-Exterior: 0; 04-09-Diametre-Interior: 0; 04-06-Area-m2: 0 m2
05-MANTENIMENT - 05-01-Fabricant: .; 05-02-Marca: .; 05-03-Model: .; 05-06-Data installacio: aa/mm/dd; 05-07-Data inici garantia: aa/mm/dd; 05-08-Data final garantia: aa/mm/dd
03-PRETACIONS - 03-01-Material: .; 03-02-RF: 0; 03-03-Pes-Kg: 0; 03-04-Potencia-W: 0; 03-05-Voltatge-V: 0; 03-06-Cabal -l/s: 0
06-ESPAIS - 06-01-Tipus us general: .; 06-01-Tipus us especific: .; 06-02-Numero: 0; 06-03-Nom: .; 06-04-Nivell: .; 06-03-Alçada lliure: 0; 06-06-Ocupació: 0; 06-05-Superficie: 0 m2
07-PROPIETATS GENERALS - 07-01-Acabat: HPL
AC_Pset_RenovationAndPhasing - Renovation Status: New
Name | In | 01-01-Nom tipus | 04-02-Amplada-m (mm) | 04-03-Alçada-m (mm) | 04-05-Perímetre-m (m2)
60.20.54 Armari | PLANTA 1ª | 60.20.54 Armari | 580 | 800 | 13.4425
2 x 60.20.54 Armari | PLANTA 1ª | 60.20.54 Armari | 580 | 800 | 11.9472
60.20.54 Armari | PLANTA 1ª | 60.20.54 Armari | 580 | 800 | 10.5235
60.20.52 Armari | PLANTA 1ª | 60.20.52 Armari | 600 | 900 | 9.83262
60.20.52 Armari | PLANTA 1ª | 60.20.52 Armari | 600 | 900 | 6.65482
60.20.52 Armari | PLANTA 2ª | 60.20.52 Armari | 600 | 900 | 14.9806

# IfcSlab: Armario Mural 27 (9)
Type - PredefinedType: FLOOR
Classification: 70.50.10.30 Arbustives (GuBIMclass CA)
01-IDENTIFICADOR - 01-01-Nom tipus: 60.20.50 Armari; 01-04-Tipus installacio: .; 01-05-Unitat de mesura: .
03-PRETACIONS - 03-01-Material: .; 03-02-RF: 0; 03-03-Pes-Kg: 0; 03-04-Potencia-W: 0; 03-05-Voltatge-V: 0; 03-06-Cabal -l/s: 0
04-DIMENSIONS - 04-07-Volum-m3: 0; 04-08-Diametre-Exterior: 0; 04-09-Diametre-Interior: 0; 04-02-Amplada-m: 380 mm; 04-06-Area-m2: 0 m2
05-MANTENIMENT - 05-01-Fabricant: .; 05-02-Marca: .; 05-03-Model: .; 05-06-Data installacio: aa/mm/dd; 05-07-Data inici garantia: aa/mm/dd; 05-08-Data final garantia: aa/mm/dd
02-LOCALIZACIÓ - 02-01-Nivell localització: .; 02-02-Codi ubicacio: .
06-ESPAIS - 06-01-Tipus us general: .; 06-01-Tipus us especific: .; 06-02-Numero: 0; 06-03-Nom: .; 06-04-Nivell: .; 06-03-Alçada lliure: 0; 06-06-Ocupació: 0; 06-05-Superficie: 0 m2
AC_Pset_RenovationAndPhasing - Renovation Status: New
07-PROPIETATS GENERALS - 07-01-Acabat: HPL
Pset_SlabCommon - IsExternal: no; LoadBearing: no
Name | In | 04-03-Alçada-m (mm) | 04-05-Perímetre-m (m2)
60.20.50 Armari | PLANTA 1ª | 400 | 2.53531
3 x 60.20.50 Armari | PLANTA 1ª | 760 | 3.86918
60.20.50 Armari | PLANTA 1ª | 763.667 | 5.1736
60.20.50 Armari | PLANTA 2ª | 760 | 6.58511
60.20.50 Armari | PLANTA 2ª | 400 | 2.53531
60.20.50 Armari | PLANTA 2ª | 760 | 6.04811
60.20.50 Armari | PLANTA 2ª | 763.667 | 5.1736

# IfcSlab: Banco 27 (3)
In: PLANTA 1ª
Type - PredefinedType: FLOOR
Classification: 70.50.10.30 Arbustives (GuBIMclass CA)
01-IDENTIFICADOR - 01-01-Nom tipus: 60.20.39 Armari; 01-04-Tipus installacio: .; 01-05-Unitat de mesura: .
02-LOCALIZACIÓ - 02-01-Nivell localització: .; 02-02-Codi ubicacio: .
03-PRETACIONS - 03-01-Material: .; 03-02-RF: 0; 03-03-Pes-Kg: 0; 03-04-Potencia-W: 0; 03-05-Voltatge-V: 0; 03-06-Cabal -l/s: 0
04-DIMENSIONS - 04-07-Volum-m3: 0; 04-08-Diametre-Exterior: 0; 04-09-Diametre-Interior: 0; 04-02-Amplada-m: 500 mm; 04-03-Alçada-m: 800 mm; 04-05-Perímetre-m: 0.9335 m2; 04-06-Area-m2: 0 m2
05-MANTENIMENT - 05-01-Fabricant: .; 05-02-Marca: .; 05-03-Model: .; 05-06-Data installacio: aa/mm/dd; 05-07-Data inici garantia: aa/mm/dd; 05-08-Data final garantia: aa/mm/dd
06-ESPAIS - 06-01-Tipus us general: .; 06-01-Tipus us especific: .; 06-02-Numero: 0; 06-03-Nom: .; 06-04-Nivell: .; 06-03-Alçada lliure: 0; 06-06-Ocupació: 0; 06-05-Superficie: 0 m2
07-PROPIETATS GENERALS - 07-01-Acabat: HPL
AC_Pset_RenovationAndPhasing - Renovation Status: New
Pset_SlabCommon - IsExternal: no; LoadBearing: no

# IfcSlab: Lavabo 02 10, 60.20.41 Armari
In: PLANTA 1ª
Type - PredefinedType: FLOOR
Classification: 70.50.10.30 Arbustives (GuBIMclass CA)
02-LOCALIZACIÓ - 02-01-Nivell localització: .; 02-02-Codi ubicacio: .
01-IDENTIFICADOR - 01-01-Nom tipus: 60.20.41 Armari; 01-04-Tipus installacio: .; 01-05-Unitat de mesura: .
04-DIMENSIONS - 04-07-Volum-m3: 0; 04-08-Diametre-Exterior: 0; 04-09-Diametre-Interior: 0; 04-02-Amplada-m: 450 mm; 04-03-Alçada-m: 850 mm; 04-05-Perímetre-m: 1.22436 m2; 04-06-Area-m2: 0 m2
03-PRETACIONS - 03-01-Material: .; 03-02-RF: 0; 03-03-Pes-Kg: 0; 03-04-Potencia-W: 0; 03-05-Voltatge-V: 0; 03-06-Cabal -l/s: 0
06-ESPAIS - 06-01-Tipus us general: .; 06-01-Tipus us especific: .; 06-02-Numero: 0; 06-03-Nom: .; 06-04-Nivell: .; 06-03-Alçada lliure: 0; 06-06-Ocupació: 0; 06-05-Superficie: 0 m2
07-PROPIETATS GENERALS - 07-01-Acabat: HPL
AC_Pset_RenovationAndPhasing - Renovation Status: New
Pset_SlabCommon - IsExternal: no; LoadBearing: no
05-MANTENIMENT - 05-01-Fabricant: .; 05-02-Marca: .; 05-03-Model: .; 05-06-Data installacio: aa/mm/dd; 05-07-Data inici garantia: aa/mm/dd; 05-08-Data final garantia: aa/mm/dd

# IfcSlab: Mampara Divisoria Oficinas 27 (20)
In: PLANTA 1ª
Type - PredefinedType: FLOOR
Classification: 70.60.10 Mobiliari exterior (GuBIMclass CA)
01-IDENTIFICADOR - 01-01-Nom tipus: 60.20.70 Armari; 01-04-Tipus installacio: .; 01-05-Unitat de mesura: .
03-PRETACIONS - 03-01-Material: .; 03-02-RF: 0; 03-03-Pes-Kg: 0; 03-04-Potencia-W: 0; 03-05-Voltatge-V: 0; 03-06-Cabal -l/s: 0
02-LOCALIZACIÓ - 02-01-Nivell localització: .; 02-02-Codi ubicacio: .
04-DIMENSIONS - 04-07-Volum-m3: 0; 04-08-Diametre-Exterior: 0; 04-09-Diametre-Interior: 0; 04-02-Amplada-m: 20 mm; 04-03-Alçada-m: 1300 mm; 04-05-Perímetre-m: 1.23537 m2; 04-06-Area-m2: 0 m2
05-MANTENIMENT - 05-01-Fabricant: .; 05-02-Marca: .; 05-03-Model: .; 05-06-Data installacio: aa/mm/dd; 05-07-Data inici garantia: aa/mm/dd; 05-08-Data final garantia: aa/mm/dd
06-ESPAIS - 06-01-Tipus us general: .; 06-01-Tipus us especific: .; 06-02-Numero: 0; 06-03-Nom: .; 06-04-Nivell: .; 06-03-Alçada lliure: 0; 06-06-Ocupació: 0; 06-05-Superficie: 0 m2
07-PROPIETATS GENERALS - 07-01-Acabat: HPL
AC_Pset_RenovationAndPhasing - Renovation Status: New
Pset_SlabCommon - IsExternal: no; LoadBearing: no

# IfcSlab: Silla 04 27 (16)
Type - PredefinedType: FLOOR
Classification: 70.50.10.30 Arbustives (GuBIMclass CA)
01-IDENTIFICADOR - 01-01-Nom tipus: 60.20.56 Armari; 01-04-Tipus installacio: .; 01-05-Unitat de mesura: .
03-PRETACIONS - 03-01-Material: .; 03-02-RF: 0; 03-03-Pes-Kg: 0; 03-04-Potencia-W: 0; 03-05-Voltatge-V: 0; 03-06-Cabal -l/s: 0
02-LOCALIZACIÓ - 02-01-Nivell localització: .; 02-02-Codi ubicacio: .
05-MANTENIMENT - 05-01-Fabricant: .; 05-02-Marca: .; 05-03-Model: .; 05-06-Data installacio: aa/mm/dd; 05-07-Data inici garantia: aa/mm/dd; 05-08-Data final garantia: aa/mm/dd
04-DIMENSIONS - 04-07-Volum-m3: 0; 04-08-Diametre-Exterior: 0; 04-09-Diametre-Interior: 0; 04-02-Amplada-m: 400 mm; 04-03-Alçada-m: 800 mm; 04-05-Perímetre-m: 1.67284 m2; 04-06-Area-m2: 0 m2
06-ESPAIS - 06-01-Tipus us general: .; 06-01-Tipus us especific: .; 06-02-Numero: 0; 06-03-Nom: .; 06-04-Nivell: .; 06-03-Alçada lliure: 0; 06-06-Ocupació: 0; 06-05-Superficie: 0 m2
07-PROPIETATS GENERALS - 07-01-Acabat: HPL
AC_Pset_RenovationAndPhasing - Renovation Status: New
Name | In
8 x 60.20.56 Armari | PLANTA 1ª
8 x 60.20.56 Armari | PLANTA 2ª

# IfcSlab: Silla 10 27 (24)
In: PLANTA 1ª
Type - PredefinedType: FLOOR
Classification: 70.50.10.30 Arbustives (GuBIMclass CA)
01-IDENTIFICADOR - 01-01-Nom tipus: 60.20.43 Armari; 01-04-Tipus installacio: .; 01-05-Unitat de mesura: .
02-LOCALIZACIÓ - 02-01-Nivell localització: .; 02-02-Codi ubicacio: .
03-PRETACIONS - 03-01-Material: .; 03-02-RF: 0; 03-03-Pes-Kg: 0; 03-04-Potencia-W: 0; 03-05-Voltatge-V: 0; 03-06-Cabal -l/s: 0
04-DIMENSIONS - 04-07-Volum-m3: 0; 04-08-Diametre-Exterior: 0; 04-09-Diametre-Interior: 0; 04-02-Amplada-m: 500 mm; 04-03-Alçada-m: 900 mm; 04-05-Perímetre-m: 1.08094 m2; 04-06-Area-m2: 0 m2
05-MANTENIMENT - 05-01-Fabricant: .; 05-02-Marca: .; 05-03-Model: .; 05-06-Data installacio: aa/mm/dd; 05-07-Data inici garantia: aa/mm/dd; 05-08-Data final garantia: aa/mm/dd
06-ESPAIS - 06-01-Tipus us general: .; 06-01-Tipus us especific: .; 06-02-Numero: 0; 06-03-Nom: .; 06-04-Nivell: .; 06-03-Alçada lliure: 0; 06-06-Ocupació: 0; 06-05-Superficie: 0 m2
07-PROPIETATS GENERALS - 07-01-Acabat: HPL
AC_Pset_RenovationAndPhasing - Renovation Status: New
Pset_SlabCommon - IsExternal: no; LoadBearing: no

# IfcSlab: Silla Composite 03 27 (16)
Type - PredefinedType: FLOOR
Classification: 70.50.10.30 Arbustives (GuBIMclass CA)
01-IDENTIFICADOR - 01-01-Nom tipus: 60.20.45 Armari; 01-04-Tipus installacio: .; 01-05-Unitat de mesura: .
02-LOCALIZACIÓ - 02-01-Nivell localització: .; 02-02-Codi ubicacio: .
03-PRETACIONS - 03-01-Material: .; 03-02-RF: 0; 03-03-Pes-Kg: 0; 03-04-Potencia-W: 0; 03-05-Voltatge-V: 0; 03-06-Cabal -l/s: 0
04-DIMENSIONS - 04-07-Volum-m3: 0; 04-08-Diametre-Exterior: 0; 04-09-Diametre-Interior: 0; 04-02-Amplada-m: 400 mm; 04-03-Alçada-m: 1050 mm; 04-05-Perímetre-m: 0.717422 m2; 04-06-Area-m2: 0 m2
05-MANTENIMENT - 05-01-Fabricant: .; 05-02-Marca: .; 05-03-Model: .; 05-06-Data installacio: aa/mm/dd; 05-07-Data inici garantia: aa/mm/dd; 05-08-Data final garantia: aa/mm/dd
06-ESPAIS - 06-01-Tipus us general: .; 06-01-Tipus us especific: .; 06-02-Numero: 0; 06-03-Nom: .; 06-04-Nivell: .; 06-03-Alçada lliure: 0; 06-06-Ocupació: 0; 06-05-Superficie: 0 m2
07-PROPIETATS GENERALS - 07-01-Acabat: HPL
AC_Pset_RenovationAndPhasing - Renovation Status: New
Pset_SlabCommon - IsExternal: no; LoadBearing: no
Name | In
7 x 60.20.45 Armari | PLANTA 1ª
9 x 60.20.45 Armari | PLANTA 2ª

# IfcSlab: Silla Diseño 03 27 (7)
Type - PredefinedType: FLOOR
Classification: 70.50.10.30 Arbustives (GuBIMclass CA)
01-IDENTIFICADOR - 01-01-Nom tipus: 60.20.46 Armari; 01-04-Tipus installacio: .; 01-05-Unitat de mesura: .
02-LOCALIZACIÓ - 02-01-Nivell localització: .; 02-02-Codi ubicacio: .
03-PRETACIONS - 03-01-Material: .; 03-02-RF: 0; 03-03-Pes-Kg: 0; 03-04-Potencia-W: 0; 03-05-Voltatge-V: 0; 03-06-Cabal -l/s: 0
04-DIMENSIONS - 04-07-Volum-m3: 0; 04-08-Diametre-Exterior: 0; 04-09-Diametre-Interior: 0; 04-02-Amplada-m: 770 mm; 04-03-Alçada-m: 770 mm; 04-05-Perímetre-m: 4.95949 m2; 04-06-Area-m2: 0 m2
06-ESPAIS - 06-01-Tipus us general: .; 06-01-Tipus us especific: .; 06-02-Numero: 0; 06-03-Nom: .; 06-04-Nivell: .; 06-03-Alçada lliure: 0; 06-06-Ocupació: 0; 06-05-Superficie: 0 m2
07-PROPIETATS GENERALS - 07-01-Acabat: HPL
05-MANTENIMENT - 05-01-Fabricant: .; 05-02-Marca: .; 05-03-Model: .; 05-06-Data installacio: aa/mm/dd; 05-07-Data inici garantia: aa/mm/dd; 05-08-Data final garantia: aa/mm/dd
AC_Pset_RenovationAndPhasing - Renovation Status: New
Pset_SlabCommon - IsExternal: no; LoadBearing: no
Name | In
4 x 60.20.46 Armari | PLANTA 1ª
3 x 60.20.46 Armari | PLANTA 2ª

# IfcTransportElement: COW~, 60.20.35 Armari
In: PLANTA 1ª
Type - PredefinedType: ELEVATOR
Classification: 60.30.10.10 Ascensors (GuBIMclass CA)
01-IDENTIFICADOR - 01-01-Nom tipus: 60.20.35 Armari; 01-04-Tipus installacio: .; 01-05-Unitat de mesura: .
02-LOCALIZACIÓ - 02-01-Nivell localització: .; 02-02-Codi ubicacio: .
03-PRETACIONS - 03-01-Material: .; 03-02-RF: 0; 03-03-Pes-Kg: 0; 03-04-Potencia-W: 0; 03-05-Voltatge-V: 0; 03-06-Cabal -l/s: 0
04-DIMENSIONS - 04-07-Volum-m3: 0; 04-08-Diametre-Exterior: 0; 04-09-Diametre-Interior: 0; 04-02-Amplada-m: 644.904 mm; 04-03-Alçada-m: 1323.86 mm; 04-05-Perímetre-m: 3.23351 m2; 04-06-Area-m2: 0 m2
05-MANTENIMENT - 05-01-Fabricant: .; 05-02-Marca: .; 05-03-Model: .; 05-06-Data installacio: aa/mm/dd; 05-07-Data inici garantia: aa/mm/dd; 05-08-Data final garantia: aa/mm/dd
06-ESPAIS - 06-01-Tipus us general: .; 06-01-Tipus us especific: .; 06-02-Numero: 0; 06-03-Nom: .; 06-04-Nivell: .; 06-03-Alçada lliure: 0; 06-06-Ocupació: 0; 06-05-Superficie: 0 m2
07-PROPIETATS GENERALS - 07-01-Acabat: HPL
AC_Pset_RenovationAndPhasing - Renovation Status: New

# IfcWallStandardCase: CR Enva Totxana 110 (50)
Classification: 40.10.10.10 Envans (GuBIMclass CA); Material: ARQ_AM246_Arrebossat_De_Guix 10 mm, ARQ_CE217_Gero 90 mm, ARQ_AM246_Arrebossat_De_Guix 10 mm
01-IDENTIFICADOR - 01-04-Tipus installacio: .; 01-05-Unitat de mesura: .
02-LOCALIZACIÓ - 02-01-Nivell localització: .; 02-02-Codi ubicacio: .
03-PRETACIONS - 03-01-Material: .; 03-02-RF: 0; 03-03-Pes-Kg: 0; 03-04-Potencia-W: 0; 03-05-Voltatge-V: 0; 03-06-Cabal -l/s: 0
04-DIMENSIONS - 04-07-Volum-m3: 0; 04-08-Diametre-Exterior: 0; 04-09-Diametre-Interior: 0; 04-02-Amplada-m: 110 mm; 04-04-Espesor-m: 110 mm; 04-06-Area-m2: 0 m2
05-MANTENIMENT - 05-01-Fabricant: .; 05-02-Marca: .; 05-03-Model: .; 05-06-Data installacio: aa/mm/dd; 05-07-Data inici garantia: aa/mm/dd; 05-08-Data final garantia: aa/mm/dd
07-PROPIETATS GENERALS - 07-01-Acabat: HPL
06-ESPAIS - 06-01-Tipus us general: .; 06-01-Tipus us especific: .; 06-02-Numero: 0; 06-03-Nom: .; 06-04-Nivell: .; 06-03-Alçada lliure: 0; 06-06-Ocupació: 0; 06-05-Superficie: 0 m2
Pset_WallCommon - IsExternal: no; LoadBearing: no
AC_Pset_RenovationAndPhasing - Renovation Status: Existing
Name | In | 01-01-Nom tipus | 04-01-Longitud-m (mm) | 04-03-Alçada-m (mm) | 04-05-Perímetre-m (m2)
2 x MS-201 | PLANTA 1ª | MS-201 | 1815 | 3350 | 5.9235
MS-201 | PLANTA 1ª | MS-201 | 6693.72 | 3350 | 17.7153
MS-201 | PLANTA 1ª | MS-201 | 8046.54 | 3350 | 20.0381
MS-201 | PLANTA 1ª | MS-201 | 2910 | 3350 | 9.009
MS-201 | PLANTA 1ª | MS-201 | 642.822 | 3650 | 2.08831
MS-201 | PLANTA 1ª | MS-201 | 3000 | 3350 | 9.339
MS-201 | PLANTA 1ª | MS-201 | 1930 | 3350 | 6.0126
MS-206 | PLANTA 1ª | MS-206 | 5690 | 3350 | 18.777
MS-201 | PLANTA 1ª | MS-201 | 13264.2 | 3350 | 37.794
MS-207 | PLANTA 1ª | MS-207 | 4460 | 3350 | 14.0514
MS-204 | PLANTA 1ª | MS-204 | 5780 | 3350 | 19.041
MS-206 | PLANTA 1ª | MS-206 | 600 | 3350 | 1.683
MS-203 | PLANTA 1ª | MS-203 | 3209.83 | 3350 | 10.5264
MS-204 | PLANTA 1ª | MS-204 | 1085 | 3350 | 3.5475
MS-203 | PLANTA 1ª | MS-203 | 5382.43 | 3350 | 17.663
MS-207 | PLANTA 1ª | MS-207 | 3060 | 3350 | 10.065
MS-206 | PLANTA 1ª | MS-206 | 3310 | 3350 | 8.88
MS-207 | PLANTA 1ª | MS-207 | 5060 | 3350 | 14.358
MS-206 | PLANTA 1ª | MS-206 | 2362.29 | 3350 | 7.49856
MS-206 | PLANTA 1ª | MS-206 | 610 | 3350 | 1.98
MS-206 | PLANTA 1ª | MS-206 | 440 | 3350 | 1.155
MS-206 | PLANTA 1ª | MS-206 | 590 | 3350 | 1.617
MS-206 | PLANTA 1ª | MS-206 | 5383.86 | 3350 | 17.7008
MS-203 | PLANTA 1ª | MS-203 | 7503.45 | 3350 | 22.9959
MS-203 | PLANTA 1ª | MS-203 | 2162.6 | 3350 | 3.92658
MS-201 | PLANTA 2ª | MS-201 | 4815 | 3350 | 12.5331
MS-201 | PLANTA 2ª | MS-201 | 14643.3 | 3350 | 43.9127
MS-201 | PLANTA 2ª | MS-201 | 15236.5 | 3350 | 45.1144
MS-201 | PLANTA 2ª | MS-201 | 4815 | 3350 | 12.2361
MS-201 | PLANTA 2ª | MS-201 | 1815 | 3350 | 5.6265
MS-201 | PLANTA 2ª | MS-201 | 4815 | 3350 | 12.5991
MS-201 | PLANTA 2ª | MS-201 | 2803.03 | 3350 | 9.21701
MS-201 | PLANTA 2ª | MS-201 | 4905 | 3350 | 13.1601
MS-201 | PLANTA 2ª | MS-201 | 565 | 3350 | 1.8315
MS-201 | PLANTA 2ª | MS-201 | 2029.78 | 3350 | 6.66528
MS-201 | PLANTA 2ª | MS-201 | 1699.94 | 3350 | 5.73282
MS-201 | PLANTA 2ª | MS-201 | 5188.21 | 3350 | 10.9801
MS-201 | PLANTA 2ª | MS-201 | 5188.21 | 3350 | 13.2751
MS-201 | PLANTA 2ª | MS-201 | 1394.6 | 3350 | 4.53618
MS-201 | PLANTA 2ª | MS-201 | 1394.6 | 3350 | 3.67818
MS-201 | PLANTA 2ª | MS-201 | 1699.94 | 3350 | 5.54382
MS-201 | PLANTA 2ª | MS-201 | 865.886 | 3350 | 2.85742
MS-201 | PLANTA 2ª | MS-201 | 4270 | 3350 | 10.1492
MS-201 | PLANTA 2ª | MS-201 | 4370 | 3350 | 13.9524
MS-201 | PLANTA 2ª | MS-201 | 700 | 3350 | 2.31
MS-201 | PLANTA 2ª | MS-201 | 5634.09 | 3350 | 18.5925
MS-201 | PLANTA 2ª | MS-201 | 12212.2 | 3350 | 33.3702
MS-206 | PLANTA 2ª | MS-206 | 5580 | 3350 | 18.414
MS-201 | PLANTA 2ª | MS-201 | 7568.45 | 3350 | 24.9759

# IfcWallStandardCase: CR Enva Totxaneta 90 (32)
Classification: 40.10.10.10 Envans (GuBIMclass CA); Material: ARQ_AM246_Arrebossat_De_Guix 10 mm, ARQ_CE217_Gero 70 mm, ARQ_AM246_Arrebossat_De_Guix 10 mm
01-IDENTIFICADOR - 01-04-Tipus installacio: .; 01-05-Unitat de mesura: .
03-PRETACIONS - 03-01-Material: .; 03-02-RF: 0; 03-03-Pes-Kg: 0; 03-04-Potencia-W: 0; 03-05-Voltatge-V: 0; 03-06-Cabal -l/s: 0
04-DIMENSIONS - 04-07-Volum-m3: 0; 04-08-Diametre-Exterior: 0; 04-09-Diametre-Interior: 0; 04-02-Amplada-m: 90 mm; 04-04-Espesor-m: 90 mm; 04-06-Area-m2: 0 m2
02-LOCALIZACIÓ - 02-01-Nivell localització: .; 02-02-Codi ubicacio: .
05-MANTENIMENT - 05-01-Fabricant: .; 05-02-Marca: .; 05-03-Model: .; 05-06-Data installacio: aa/mm/dd; 05-07-Data inici garantia: aa/mm/dd; 05-08-Data final garantia: aa/mm/dd
06-ESPAIS - 06-01-Tipus us general: .; 06-01-Tipus us especific: .; 06-02-Numero: 0; 06-03-Nom: .; 06-04-Nivell: .; 06-03-Alçada lliure: 0; 06-06-Ocupació: 0; 06-05-Superficie: 0 m2
07-PROPIETATS GENERALS - 07-01-Acabat: HPL
AC_Pset_RenovationAndPhasing - Renovation Status: Existing
Pset_WallCommon - IsExternal: no; LoadBearing: no
Name | In | 01-01-Nom tipus | 04-01-Longitud-m (mm) | 04-03-Alçada-m (mm) | 04-05-Perímetre-m (m2)
MS-204 | PLANTA 1ª | MS-204 | 4572.29 | 3350 | 14.4946
MS-208 | PLANTA 1ª | MS-208 | 330 | 3350 | 0.825
MS-209 | PLANTA 1ª | MS-209 | 330 | 3350 | 0.791999
MS-210 | PLANTA 1ª | MS-210 | 260 | 3350 | 0.825
2 x MS-201 | PLANTA 2ª | MS-201 | 450 | 3350 | 1.485
MS-201 | PLANTA 2ª | MS-201 | 1905 | 3350 | 6.0225
MS-201 | PLANTA 2ª | MS-201 | 1905 | 3350 | 5.9895
MS-201 | PLANTA 2ª | MS-201 | 5041.79 | 3350 | 15.4169
MS-201 | PLANTA 2ª | MS-201 | 425 | 3350 | 0.891
MS-201 | PLANTA 2ª | MS-201 | 340 | 3350 | 1.089
MS-201 | PLANTA 2ª | MS-201 | 627.116 | 3350 | 1.69361
MS-203 | PLANTA 2ª | MS-203 | 3708.53 | 3350 | 10.7697
MS-201 | PLANTA 2ª | MS-201 | 6599 | 3350 | 20.5557
MS-203 | PLANTA 2ª | MS-203 | 3608.53 | 3350 | 6.85751
MS-203 | PLANTA 2ª | MS-203 | 12120 | 3350 | 36.1829
MS-203 | PLANTA 2ª | MS-203 | 4969.25 | 3350 | 11.2715
MS-203 | PLANTA 2ª | MS-203 | 5267.91 | 3350 | 15.2301
MS-203 | PLANTA 2ª | MS-203 | 1879.32 | 3350 | 3.19576
MS-203 | PLANTA 2ª | MS-203 | 5267.91 | 3350 | 17.1531
MS-203 | PLANTA 2ª | MS-203 | 10202.3 | 3350 | 28.4354
5 x MS-203 | PLANTA 2ª | MS-203 | 2455.98 | 3350 | 8.03874
MS-203 | PLANTA 2ª | MS-203 | 2525.98 | 3350 | 8.03874
MS-203 | PLANTA 2ª | MS-203 | 3872.15 | 3350 | 10.4141
MS-203 | PLANTA 2ª | MS-203 | 10042.3 | 3350 | 33.0404
MS-203 | PLANTA 2ª | MS-203 | 1899.9 | 3650 | 2.49327
MS-204 | PLANTA 2ª | MS-204 | 3446.59 | 3350 | 11.3738
MS-203 | PLANTA 2ª | MS-203 | 3053.53 | 3350 | 10.0107

# IfcWallStandardCase: CR Pladur 70 / 2H+2H 122 (3)
In: PLANTA 1ª
Classification: 40.10.10.10 Envans (GuBIMclass CA); Material: ARQ_CG063_Guix_Laminat_Hydro 13 mm, ARQ_CG063_Guix_Laminat_Hydro 13 mm, ARQ_AI033_Aillament_Llana_De_Roca 70 mm, ARQ_CG063_Guix_Laminat_Hydro 13 mm, ARQ_CG063_Guix_Laminat_Hydro 13 mm
01-IDENTIFICADOR - 01-01-Nom tipus: MS-205; 01-04-Tipus installacio: .; 01-05-Unitat de mesura: .
02-LOCALIZACIÓ - 02-01-Nivell localització: .; 02-02-Codi ubicacio: .
04-DIMENSIONS - 04-07-Volum-m3: 0; 04-08-Diametre-Exterior: 0; 04-09-Diametre-Interior: 0; 04-02-Amplada-m: 122 mm; 04-03-Alçada-m: 3350 mm; 04-04-Espesor-m: 122 mm; 04-06-Area-m2: 0 m2
03-PRETACIONS - 03-01-Material: .; 03-02-RF: 0; 03-03-Pes-Kg: 0; 03-04-Potencia-W: 0; 03-05-Voltatge-V: 0; 03-06-Cabal -l/s: 0
05-MANTENIMENT - 05-01-Fabricant: .; 05-02-Marca: .; 05-03-Model: .; 05-06-Data installacio: aa/mm/dd; 05-07-Data inici garantia: aa/mm/dd; 05-08-Data final garantia: aa/mm/dd
06-ESPAIS - 06-01-Tipus us general: .; 06-01-Tipus us especific: .; 06-02-Numero: 0; 06-03-Nom: .; 06-04-Nivell: .; 06-03-Alçada lliure: 0; 06-06-Ocupació: 0; 06-05-Superficie: 0 m2
07-PROPIETATS GENERALS - 07-01-Acabat: HPL
AC_Pset_RenovationAndPhasing - Renovation Status: New
Pset_WallCommon - IsExternal: no; LoadBearing: no
Name | 04-01-Longitud-m (mm) | 04-05-Perímetre-m (m2)
MS-205 | 1551.95 | 4.86863
MS-205 | 1557.6 | 4.88697
MS-205 | 1563.23 | 4.90415

# IfcWallStandardCase: CR Pladur 70 HPL 1 cara 134 (14)
Classification: 40.10.10.10 Envans (GuBIMclass CA); Material: Panel de Yeso Laminado 13 mm, Panel de Yeso Laminado 13 mm, ARQ_AI033_Aillament_Llana_De_Roca 70 mm, Panel de Yeso Laminado 13 mm, Panel de Yeso Laminado 13 mm, ARQ_EN271_Camara_Aire 6 mm, ARQ_FU093_Panellat_HPL 6 mm
01-IDENTIFICADOR - 01-04-Tipus installacio: .; 01-05-Unitat de mesura: .
02-LOCALIZACIÓ - 02-01-Nivell localització: .; 02-02-Codi ubicacio: .
05-MANTENIMENT - 05-01-Fabricant: .; 05-02-Marca: .; 05-03-Model: .; 05-06-Data installacio: aa/mm/dd; 05-07-Data inici garantia: aa/mm/dd; 05-08-Data final garantia: aa/mm/dd
04-DIMENSIONS - 04-07-Volum-m3: 0; 04-08-Diametre-Exterior: 0; 04-09-Diametre-Interior: 0; 04-02-Amplada-m: 134 mm; 04-04-Espesor-m: 134 mm; 04-06-Area-m2: 0 m2
03-PRETACIONS - 03-01-Material: .; 03-02-RF: 0; 03-03-Pes-Kg: 0; 03-04-Potencia-W: 0; 03-05-Voltatge-V: 0; 03-06-Cabal -l/s: 0
06-ESPAIS - 06-01-Tipus us general: .; 06-01-Tipus us especific: .; 06-02-Numero: 0; 06-03-Nom: .; 06-04-Nivell: .; 06-03-Alçada lliure: 0; 06-06-Ocupació: 0; 06-05-Superficie: 0 m2
AC_Pset_RenovationAndPhasing - Renovation Status: New
Pset_WallCommon - IsExternal: no; LoadBearing: no
07-PROPIETATS GENERALS - 07-01-Acabat: HPL
Name | In | 01-01-Nom tipus | 04-01-Longitud-m (mm) | 04-03-Alçada-m (mm) | 04-05-Perímetre-m (m2)
MS-212 | PLANTA 1ª | MS-212 | 1490 | 3350 | 2.6244
MS-213 | PLANTA 1ª | MS-213 | 2895.83 | 3350 | 8.97659
MS-213 | PLANTA 1ª | MS-213 | 2894.83 | 3350 | 8.97659
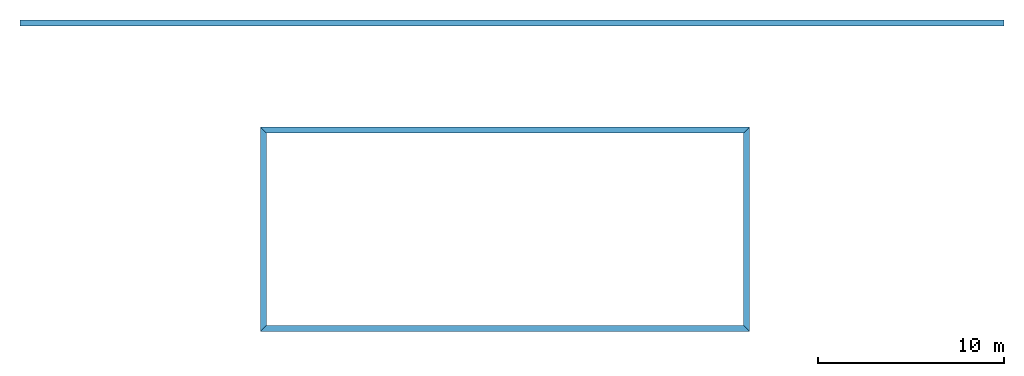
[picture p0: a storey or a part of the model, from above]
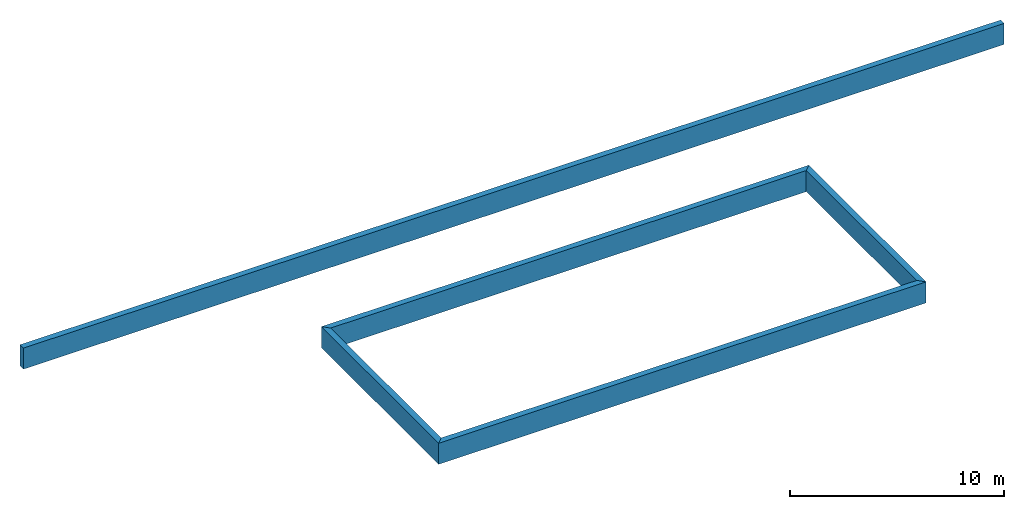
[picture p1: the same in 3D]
Properties of the parts of a building model (IFC2X3), part 2 of 2

# IfcWallStandardCase: CR Pladur 70 HPL 1 cara 134 (14)
Name | In | 01-01-Nom tipus | 04-01-Longitud-m (mm) | 04-03-Alçada-m (mm) | 04-05-Perímetre-m (m2)
MS-212 | PLANTA 1ª | MS-212 | 814.146 | 3350 | 2.24926
MS-212 | PLANTA 1ª | MS-212 | 10902.3 | 3350 | 27.1483
MS-212 | PLANTA 1ª | MS-212 | 219.936 | 3350 | 0.298334
MS-213 | PLANTA 1ª | MS-213 | 9411.74 | 3350 | 22.9556
MS-212 | PLANTA 2ª | MS-212 | 6977.21 | 3650 | 20.2091
MS-212 | PLANTA 2ª | MS-212 | 11317 | 3650 | 28.0147
MS-212 | PLANTA 2ª | MS-212 | 5717.21 | 3650 | 12.2587
MS-211 | PLANTA 2ª | MS-211 | 3143.53 | 3650 | 9.96831
MS-211 | PLANTA 2ª | MS-211 | 3131.53 | 3650 | 10.3278
MS-211 | PLANTA 2ª | MS-211 | 5459 | 3650 | 15.2738
MS-213 | PLANTA 2ª | MS-213 | 2760.83 | 3350 | 8.57753

# IfcWallStandardCase: CR Pladur 70 HPL 2 cares 146 (23)
Classification: 40.10.10.10 Envans (GuBIMclass CA); Material: ARQ_FU093_Panellat_HPL 6 mm, ARQ_EN271_Camara_Aire 6 mm, Panel de Yeso Laminado 13 mm, Panel de Yeso Laminado 13 mm, ARQ_AI033_Aillament_Llana_De_Roca 70 mm, Panel de Yeso Laminado 13 mm, Panel de Yeso Laminado 13 mm, ARQ_EN271_Camara_Aire 6 mm, ARQ_FU093_Panellat_HPL 6 mm
01-IDENTIFICADOR - 01-04-Tipus installacio: .; 01-05-Unitat de mesura: .
03-PRETACIONS - 03-01-Material: .; 03-02-RF: 0; 03-03-Pes-Kg: 0; 03-04-Potencia-W: 0; 03-05-Voltatge-V: 0; 03-06-Cabal -l/s: 0
02-LOCALIZACIÓ - 02-01-Nivell localització: .; 02-02-Codi ubicacio: .
04-DIMENSIONS - 04-07-Volum-m3: 0; 04-08-Diametre-Exterior: 0; 04-09-Diametre-Interior: 0; 04-02-Amplada-m: 146 mm; 04-04-Espesor-m: 146 mm; 04-06-Area-m2: 0 m2
05-MANTENIMENT - 05-01-Fabricant: .; 05-02-Marca: .; 05-03-Model: .; 05-06-Data installacio: aa/mm/dd; 05-07-Data inici garantia: aa/mm/dd; 05-08-Data final garantia: aa/mm/dd
06-ESPAIS - 06-01-Tipus us general: .; 06-01-Tipus us especific: .; 06-02-Numero: 0; 06-03-Nom: .; 06-04-Nivell: .; 06-03-Alçada lliure: 0; 06-06-Ocupació: 0; 06-05-Superficie: 0 m2
AC_Pset_RenovationAndPhasing - Renovation Status: New
Pset_WallCommon - IsExternal: no; LoadBearing: no
07-PROPIETATS GENERALS - 07-01-Acabat: HPL
Name | In | 01-01-Nom tipus | 04-01-Longitud-m (mm) | 04-03-Alçada-m (mm) | 04-05-Perímetre-m (m2)
MS-202 | PLANTA 1ª | MS-202 | 5050 | 3650 | 11.1637
MS-211 | PLANTA 1ª | MS-211 | 2172.22 | 3350 | 7.16832
MS-212 | PLANTA 1ª | MS-212 | 5125 | 3350 | 9.48845
MS-215 | PLANTA 1ª | MS-215 | 2786.83 | 3350 | 8.87106
MS-214 | PLANTA 1ª | MS-214 | 854 | 3350 | 2.69117
MS-211 | PLANTA 1ª | MS-211 | 15042.2 | 3350 | 36.2364
MS-205 | PLANTA 1ª | MS-205 | 3156.07 | 3350 | 9.04552
MS-214 | PLANTA 1ª | MS-214 | 1740.17 | 3350 | 5.29715
MS-225 | PLANTA 1ª | MS-225 | 5465 | 3350 | 15.4836
MS-241 | PLANTA 1ª | MS-241 | 2894.83 | 3350 | 8.87106
MS-214 | PLANTA 1ª | MS-214 | 1181.35 | 3350 | 3.89847
MS-205 | PLANTA 1ª | MS-205 | 1373.69 | 3350 | 2.25508
MS-214 | PLANTA 1ª | MS-214 | 500.432 | 3350 | 1.65042
MS-214 | PLANTA 2ª | MS-214 | 1041.35 | 3350 | 3.43438
MS-211 | PLANTA 2ª | MS-211 | 1742.22 | 3650 | 5.3039
MS-211 | PLANTA 2ª | MS-211 | 984 | 3650 | 2.8033
MS-212 | PLANTA 2ª | MS-212 | 5180 | 3650 | 9.76309
MS-211 | PLANTA 2ª | MS-211 | 197 | 3650 | 0.606814
MS-211 | PLANTA 2ª | MS-211 | 4563.79 | 3650 | 14.8095
MS-202 | PLANTA 2ª | MS-202 | 5050 | 3650 | 11.1637
MS-214 | PLANTA 2ª | MS-214 | 805.255 | 3350 | 2.62275
MS-211 | PLANTA 2ª | MS-211 | 3023.36 | 3650 | 9.76327
MS-225 | PLANTA 2ª | MS-225 | 5718.21 | 3350 | 15.8313

# IfcWallStandardCase: CR Pladur 70 mixte HPL 1 134 (6)
In: PLANTA 1ª
Classification: 40.10.10.10 Envans (GuBIMclass CA); Material: ARQ_FU093_Panellat_HPL 6 mm, ARQ_EN271_Camara_Aire 6 mm, Panel de Yeso Laminado 13 mm, Panel de Yeso Laminado 13 mm, ARQ_AI033_Aillament_Llana_De_Roca 70 mm, ARQ_CG063_Guix_Laminat_Hydro 13 mm, ARQ_CG063_Guix_Laminat_Hydro 13 mm
01-IDENTIFICADOR - 01-04-Tipus installacio: .; 01-05-Unitat de mesura: .
03-PRETACIONS - 03-01-Material: .; 03-02-RF: 0; 03-03-Pes-Kg: 0; 03-04-Potencia-W: 0; 03-05-Voltatge-V: 0; 03-06-Cabal -l/s: 0
04-DIMENSIONS - 04-07-Volum-m3: 0; 04-08-Diametre-Exterior: 0; 04-09-Diametre-Interior: 0; 04-02-Amplada-m: 134 mm; 04-03-Alçada-m: 3350 mm; 04-04-Espesor-m: 134 mm; 04-06-Area-m2: 0 m2
02-LOCALIZACIÓ - 02-01-Nivell localització: .; 02-02-Codi ubicacio: .
05-MANTENIMENT - 05-01-Fabricant: .; 05-02-Marca: .; 05-03-Model: .; 05-06-Data installacio: aa/mm/dd; 05-07-Data inici garantia: aa/mm/dd; 05-08-Data final garantia: aa/mm/dd
07-PROPIETATS GENERALS - 07-01-Acabat: HPL
AC_Pset_RenovationAndPhasing - Renovation Status: New
Pset_WallCommon - IsExternal: no; LoadBearing: no
06-ESPAIS - 06-01-Tipus us general: .; 06-01-Tipus us especific: .; 06-02-Numero: 0; 06-03-Nom: .; 06-04-Nivell: .; 06-03-Alçada lliure: 0; 06-06-Ocupació: 0; 06-05-Superficie: 0 m2
Name | 01-01-Nom tipus | 04-01-Longitud-m (mm) | 04-05-Perímetre-m (m2)
MS-205 | MS-205 | 9273.82 | 20.0496
MS-205 | MS-205 | 9226.99 | 23.8549
MS-205 | MS-205 | 3301.5 | 8.70159
MS-205 | MS-205 | 1643.24 | 3.0471
MS-205 | MS-205 | 1648.13 | 5.26669
MS-211 | MS-211 | 2099.19 | 6.92733

# IfcWallStandardCase: CR Revestiment HPL 60 (6)
Classification: 40.10.10.10 Envans (GuBIMclass CA); Material: ARQ_AM246_Arrebossat_De_Guix 20 mm, ARQ_EN271_Camara_Aire 40 mm
01-IDENTIFICADOR - 01-04-Tipus installacio: .; 01-05-Unitat de mesura: .
02-LOCALIZACIÓ - 02-01-Nivell localització: .; 02-02-Codi ubicacio: .
03-PRETACIONS - 03-01-Material: .; 03-02-RF: 0; 03-03-Pes-Kg: 0; 03-04-Potencia-W: 0; 03-05-Voltatge-V: 0; 03-06-Cabal -l/s: 0
04-DIMENSIONS - 04-07-Volum-m3: 0; 04-08-Diametre-Exterior: 0; 04-09-Diametre-Interior: 0; 04-02-Amplada-m: 60 mm; 04-03-Alçada-m: 3350 mm; 04-04-Espesor-m: 60 mm; 04-06-Area-m2: 0 m2
05-MANTENIMENT - 05-01-Fabricant: .; 05-02-Marca: .; 05-03-Model: .; 05-06-Data installacio: aa/mm/dd; 05-07-Data inici garantia: aa/mm/dd; 05-08-Data final garantia: aa/mm/dd
06-ESPAIS - 06-01-Tipus us general: .; 06-01-Tipus us especific: .; 06-02-Numero: 0; 06-03-Nom: .; 06-04-Nivell: .; 06-03-Alçada lliure: 0; 06-06-Ocupació: 0; 06-05-Superficie: 0 m2
07-PROPIETATS GENERALS - 07-01-Acabat: HPL
AC_Pset_RenovationAndPhasing - Renovation Status: New
Pset_WallCommon - IsExternal: no; LoadBearing: no
Name | In | 01-01-Nom tipus | 04-01-Longitud-m (mm) | 04-05-Perímetre-m (m2)
MS-214 | PLANTA 1ª | MS-214 | 1337.49 | 4.41371
MS-214 | PLANTA 1ª | MS-214 | 24658.6 | 81.3733
MS-214 | PLANTA 1ª | MS-214 | 10644.4 | 35.1266
MS-215 | PLANTA 2ª | MS-215 | 7115.15 | 23.48
MS-215 | PLANTA 2ª | MS-215 | 17514 | 57.7961
MS-215 | PLANTA 2ª | MS-215 | 6723.97 | 22.1891

# IfcWallStandardCase: CR- MAMPARA 70 (8)
Classification: 40.10.10.10 Envans (GuBIMclass CA); Material: Panel de Yeso Laminado 5 mm, ARQ_AI033_Aillament_Llana_De_Roca 60 mm, Panel de Yeso Laminado 5 mm
01-IDENTIFICADOR - 01-04-Tipus installacio: .; 01-05-Unitat de mesura: .
02-LOCALIZACIÓ - 02-01-Nivell localització: .; 02-02-Codi ubicacio: .
03-PRETACIONS - 03-01-Material: .; 03-02-RF: 0; 03-03-Pes-Kg: 0; 03-04-Potencia-W: 0; 03-05-Voltatge-V: 0; 03-06-Cabal -l/s: 0
05-MANTENIMENT - 05-01-Fabricant: .; 05-02-Marca: .; 05-03-Model: .; 05-06-Data installacio: aa/mm/dd; 05-07-Data inici garantia: aa/mm/dd; 05-08-Data final garantia: aa/mm/dd
06-ESPAIS - 06-01-Tipus us general: .; 06-01-Tipus us especific: .; 06-02-Numero: 0; 06-03-Nom: .; 06-04-Nivell: .; 06-03-Alçada lliure: 0; 06-06-Ocupació: 0; 06-05-Superficie: 0 m2
07-PROPIETATS GENERALS - 07-01-Acabat: HPL
04-DIMENSIONS - 04-07-Volum-m3: 0; 04-08-Diametre-Exterior: 0; 04-09-Diametre-Interior: 0; 04-02-Amplada-m: 70 mm; 04-04-Espesor-m: 70 mm; 04-06-Area-m2: 0 m2
Pset_WallCommon - IsExternal: no; LoadBearing: no
AC_Pset_RenovationAndPhasing - Renovation Status: New
Name | In | 01-01-Nom tipus | 04-01-Longitud-m (mm) | 04-03-Alçada-m (mm) | 04-05-Perímetre-m (m2)
MS-212 | PLANTA 1ª | MS-212 | 4780.85 | 3350 | 5.30401
MS-214 | PLANTA 1ª | MS-214 | 3394.03 | 3350 | 4.07284
MS-214 | PLANTA 1ª | MS-214 | 7792.39 | 3350 | 9.43087
MS-212 | PLANTA 1ª | MS-212 | 5462.06 | 3350 | 6.46502
MS-214 | PLANTA 1ª | MS-214 | 1640.62 | 3350 | 1.96875
MS-214 | PLANTA 2ª | MS-214 | 4737.12 | 3350 | 5.7629
MS-211 | PLANTA 2ª | MS-211 | 3477.73 | 3650 | 4.21827
MS-214 | PLANTA 2ª | MS-214 | 3116.78 | 3350 | 3.74236

# IfcWallStandardCase: Pladur 70 / 2N+2N 122 (5)
Classification: 40.10.10.10 Envans (GuBIMclass CA); Material: Panel de Yeso Laminado 13 mm, Panel de Yeso Laminado 13 mm, ARQ_AI033_Aillament_Llana_De_Roca 70 mm, Panel de Yeso Laminado 13 mm, Panel de Yeso Laminado 13 mm
01-IDENTIFICADOR - 01-04-Tipus installacio: .; 01-05-Unitat de mesura: .
02-LOCALIZACIÓ - 02-01-Nivell localització: .; 02-02-Codi ubicacio: .
04-DIMENSIONS - 04-07-Volum-m3: 0; 04-08-Diametre-Exterior: 0; 04-09-Diametre-Interior: 0; 04-02-Amplada-m: 122 mm; 04-04-Espesor-m: 122 mm; 04-06-Area-m2: 0 m2
03-PRETACIONS - 03-01-Material: .; 03-02-RF: 0; 03-03-Pes-Kg: 0; 03-04-Potencia-W: 0; 03-05-Voltatge-V: 0; 03-06-Cabal -l/s: 0
05-MANTENIMENT - 05-01-Fabricant: .; 05-02-Marca: .; 05-03-Model: .; 05-06-Data installacio: aa/mm/dd; 05-07-Data inici garantia: aa/mm/dd; 05-08-Data final garantia: aa/mm/dd
06-ESPAIS - 06-01-Tipus us general: .; 06-01-Tipus us especific: .; 06-02-Numero: 0; 06-03-Nom: .; 06-04-Nivell: .; 06-03-Alçada lliure: 0; 06-06-Ocupació: 0; 06-05-Superficie: 0 m2
AC_Pset_RenovationAndPhasing - Renovation Status: New
Pset_WallCommon - IsExternal: no; LoadBearing: no
07-PROPIETATS GENERALS - 07-01-Acabat: HPL
Name | In | 01-01-Nom tipus | 04-01-Longitud-m (mm) | 04-03-Alçada-m (mm) | 04-05-Perímetre-m (m2)
MS-212 | PLANTA 1ª | MS-212 | 2851.83 | 3350 | 9.13713
MS-213 | PLANTA 1ª | MS-213 | 3011.83 | 3350 | 8.93372
MS-212 | PLANTA 2ª | MS-212 | 3125.53 | 3650 | 10.0475
MS-225 | PLANTA 2ª | MS-225 | 3736.1 | 3650 | 12.1502
MS-225 | PLANTA 2ª | MS-225 | 5625.21 | 3650 | 18.2266

# IfcWallStandardCase: Pladur 70 Foc/ 2F+2F 122 (6)
Classification: 40.10.10.10 Envans (GuBIMclass CA); Material: ARQ_CG062_Guix_Laminat_Foc 13 mm, ARQ_CG062_Guix_Laminat_Foc 13 mm, ARQ_AI033_Aillament_Llana_De_Roca 70 mm, ARQ_CG062_Guix_Laminat_Foc 13 mm, ARQ_CG062_Guix_Laminat_Foc 13 mm
01-IDENTIFICADOR - 01-04-Tipus installacio: .; 01-05-Unitat de mesura: .
02-LOCALIZACIÓ - 02-01-Nivell localització: .; 02-02-Codi ubicacio: .
03-PRETACIONS - 03-01-Material: .; 03-02-RF: 0; 03-03-Pes-Kg: 0; 03-04-Potencia-W: 0; 03-05-Voltatge-V: 0; 03-06-Cabal -l/s: 0
04-DIMENSIONS - 04-07-Volum-m3: 0; 04-08-Diametre-Exterior: 0; 04-09-Diametre-Interior: 0; 04-02-Amplada-m: 122 mm; 04-03-Alçada-m: 3350 mm; 04-04-Espesor-m: 122 mm; 04-06-Area-m2: 0 m2
05-MANTENIMENT - 05-01-Fabricant: .; 05-02-Marca: .; 05-03-Model: .; 05-06-Data installacio: aa/mm/dd; 05-07-Data inici garantia: aa/mm/dd; 05-08-Data final garantia: aa/mm/dd
06-ESPAIS - 06-01-Tipus us general: .; 06-01-Tipus us especific: .; 06-02-Numero: 0; 06-03-Nom: .; 06-04-Nivell: .; 06-03-Alçada lliure: 0; 06-06-Ocupació: 0; 06-05-Superficie: 0 m2
07-PROPIETATS GENERALS - 07-01-Acabat: HPL
AC_Pset_RenovationAndPhasing - Renovation Status: New
Pset_WallCommon - IsExternal: no; LoadBearing: no
Name | In | 01-01-Nom tipus | 04-01-Longitud-m (mm) | 04-05-Perímetre-m (m2)
MS-216 | PLANTA 1ª | MS-216 | 600 | 2.01
MS-217 | PLANTA 1ª | MS-217 | 1987 | 3.10536
MS-216 | PLANTA 1ª | MS-216 | 597 | 1.6348
MS-216 | PLANTA 2ª | MS-216 | 652 | 1.81905
MS-216 | PLANTA 2ª | MS-216 | 668.215 | 2.23852
MS-217 | PLANTA 2ª | MS-217 | 1987 | 3.10536

# IfcWallStandardCase: Pladur Tras 40 / 1N +HPL 65 (84)
Classification: 40.10.10.10 Envans (GuBIMclass CA); Material: ARQ_FU093_Panellat_HPL 6 mm, ARQ_EN271_Camara_Aire 6 mm, Panel de Yeso Laminado 13 mm, ARQ_AI033_Aillament_Llana_De_Roca 40 mm
01-IDENTIFICADOR - 01-04-Tipus installacio: .; 01-05-Unitat de mesura: .
02-LOCALIZACIÓ - 02-01-Nivell localització: .; 02-02-Codi ubicacio: .
06-ESPAIS - 06-01-Tipus us general: .; 06-01-Tipus us especific: .; 06-02-Numero: 0; 06-03-Nom: .; 06-04-Nivell: .; 06-03-Alçada lliure: 0; 06-06-Ocupació: 0; 06-05-Superficie: 0 m2
04-DIMENSIONS - 04-02-Amplada-m: 65 mm; 04-04-Espesor-m: 65 mm; 04-06-Area-m2: 0 m2; 04-07-Volum-m3: 0; 04-08-Diametre-Exterior: 0; 04-09-Diametre-Interior: 0
Pset_WallCommon - IsExternal: no; LoadBearing: no
07-PROPIETATS GENERALS - 07-01-Acabat: HPL
05-MANTENIMENT - 05-01-Fabricant: .; 05-02-Marca: .; 05-03-Model: .; 05-06-Data installacio: aa/mm/dd; 05-07-Data inici garantia: aa/mm/dd; 05-08-Data final garantia: aa/mm/dd
03-PRETACIONS - 03-01-Material: .; 03-02-RF: 0; 03-03-Pes-Kg: 0; 03-04-Potencia-W: 0; 03-05-Voltatge-V: 0; 03-06-Cabal -l/s: 0
Name | In | 01-01-Nom tipus | 04-01-Longitud-m (mm) | 04-03-Alçada-m (mm) | 04-05-Perímetre-m (m2) | Renovation Status
MS-217 | PLANTA 1ª | MS-217 | 2535 | 3350 | 8.22607 | New
MS-237 | PLANTA 1ª | MS-237 | 759 | 3350 | 2.46295 | New
MS-237 | PLANTA 1ª | MS-237 | 477 | 3350 | 1.44284 | New
MS-232 | PLANTA 1ª | MS-232 | 235 | 3350 | 0.7755 | Existing
MS-241 | PLANTA 1ª | MS-241 | 1994.08 | 3350 | 6.45116 | New
MS-232 | PLANTA 1ª | MS-232 | 1010 | 3350 | 3.33266 | Existing
MS-205 | PLANTA 1ª | MS-205 | 250.585 | 3350 | 0.504873 | New
MS-206 | PLANTA 1ª | MS-206 | 524.001 | 3350 | 1.70038 | New
MS-207 | PLANTA 1ª | MS-207 | 284.585 | 3350 | 0.707474 | New
MS-208 | PLANTA 1ª | MS-208 | 235 | 3350 | 0.544171 | New
MS-209 | PLANTA 1ª | MS-209 | 477.215 | 3350 | 1.57385 | New
MS-210 | PLANTA 1ª | MS-210 | 574 | 3350 | 1.89305 | New
MS-211 | PLANTA 1ª | MS-211 | 212.215 | 3350 | 0.403195 | New
MS-214 | PLANTA 1ª | MS-214 | 315 | 3350 | 0.9141 | New
MS-215 | PLANTA 1ª | MS-215 | 621.405 | 3350 | 2.05064 | New
MS-216 | PLANTA 1ª | MS-216 | 309 | 3350 | 0.8943 | New
MS-219 | PLANTA 1ª | MS-219 | 450 | 3350 | 1.485 | New
MS-218 | PLANTA 1ª | MS-218 | 395 | 3350 | 1.1781 | New
MS-247 | PLANTA 1ª | MS-247 | 3355 | 3350 | 10.887 | New
MS-220 | PLANTA 1ª | MS-220 | 389 | 3350 | 1.1583 | New
MS-250 | PLANTA 1ª | MS-250 | 284.585 | 3350 | 0.707474 | New
MS-249 | PLANTA 1ª | MS-249 | 844.597 | 3350 | 2.61753 | New
MS-223 | PLANTA 1ª | MS-223 | 302 | 3350 | 0.856681 | New
MS-227 | PLANTA 1ª | MS-227 | 474 | 3350 | 1.56325 | New
MS-226 | PLANTA 1ª | MS-226 | 574 | 3350 | 1.89305 | New
MS-228 | PLANTA 1ª | MS-228 | 466 | 3350 | 1.41154 | New
MS-233 | PLANTA 1ª | MS-233 | 2376 | 3350 | 7.43429 | New
MS-234 | PLANTA 1ª | MS-234 | 625 | 3350 | 1.947 | New
MS-235 | PLANTA 1ª | MS-235 | 427 | 3350 | 1.26323 | New
MS-212 | PLANTA 1ª | MS-212 | 3180 | 3350 | 10.3206 | New
MS-238 | PLANTA 1ª | MS-238 | 215 | 3350 | 0.4125 | New
MS-239 | PLANTA 1ª | MS-239 | 574.002 | 3350 | 1.89329 | New
MS-240 | PLANTA 1ª | MS-240 | 209 | 3350 | 0.389541 | New
MS-241 | PLANTA 1ª | MS-241 | 5300 | 3350 | 17.2019 | New
MS-242 | PLANTA 1ª | MS-242 | 215 | 3350 | 0.41235 | New
MS-243 | PLANTA 1ª | MS-243 | 504 | 3350 | 1.66219 | New
MS-217 | PLANTA 1ª | MS-217 | 3257.8 | 3350 | 10.1718 | New
MS-241 | PLANTA 1ª | MS-241 | 3932.5 | 3350 | 12.9694 | New
MS-241 | PLANTA 1ª | MS-241 | 2576.42 | 3350 | 8.39149 | New
MS-241 | PLANTA 1ª | MS-241 | 897.5 | 3350 | 2.95996 | New
MS-241 | PLANTA 1ª | MS-241 | 1892.5 | 3350 | 6.11614 | New
MS-241 | PLANTA 1ª | MS-241 | 838 | 3350 | 2.6384 | New
MS-217 | PLANTA 1ª | MS-217 | 251.519 | 3350 | 0.692565 | New
MS-243 | PLANTA 2ª | MS-243 | 209 | 3650 | 0.392562 | New
MS-212 | PLANTA 2ª | MS-212 | 580.002 | 3350 | 1.88211 | New
MS-212 | PLANTA 2ª | MS-212 | 130 | 3350 | 0.230533 | New
MS-212 | PLANTA 2ª | MS-212 | 88.2149 | 3350 | 0.205132 | New
MS-233 | PLANTA 2ª | MS-233 | 2306 | 3350 | 7.20799 | New
MS-226 | PLANTA 2ª | MS-226 | 445 | 3350 | 1.3398 | New
MS-228 | PLANTA 2ª | MS-228 | 439 | 3350 | 1.32001 | New
MS-231 | PLANTA 2ª | MS-231 | 407 | 3350 | 1.21696 | New
3 x MS-227 | PLANTA 2ª | MS-227 | 474 | 3350 | 1.56325 | New
MS-243 | PLANTA 2ª | MS-243 | 670 | 3650 | 2.20966 | New
MS-243 | PLANTA 2ª | MS-243 | 3157.53 | 3650 | 10.1992 | New
MS-243 | PLANTA 2ª | MS-243 | 2794.49 | 3650 | 9.02163 | New
MS-243 | PLANTA 2ª | MS-243 | 915.952 | 3650 | 2.55298 | New
MS-243 | PLANTA 2ª | MS-243 | 897.5 | 3650 | 2.95996 | New
MS-243 | PLANTA 2ª | MS-243 | 3253.93 | 3650 | 10.5171 | New
MS-243 | PLANTA 2ª | MS-243 | 416.171 | 3650 | 0.425427 | New
MS-243 | PLANTA 2ª | MS-243 | 319.002 | 3650 | 1.02874 | New
MS-243 | PLANTA 2ª | MS-243 | 210.822 | 3650 | 0.50071 | New
MS-243 | PLANTA 2ª | MS-243 | 2800.5 | 3650 | 9.23605 | New
MS-243 | PLANTA 2ª | MS-243 | 219 | 3650 | 0.495109 | New
MS-212 | PLANTA 2ª | MS-212 | 3220 | 3350 | 10.6197 | New
MS-212 | PLANTA 2ª | MS-212 | 229 | 3350 | 0.524383 | New
MS-212 | PLANTA 2ª | MS-212 | 477.215 | 3350 | 1.57385 | New
MS-212 | PLANTA 2ª | MS-212 | 450.002 | 3350 | 1.48501 | New
MS-212 | PLANTA 2ª | MS-212 | 5285 | 3350 | 17.43 | New
MS-228 | PLANTA 2ª | MS-228 | 466 | 3350 | 1.41154 | New
MS-226 | PLANTA 2ª | MS-226 | 574 | 3350 | 1.89284 | New
MS-228 | PLANTA 2ª | MS-228 | 439 | 3350 | 1.31999 | New
MS-226 | PLANTA 2ª | MS-226 | 445 | 3350 | 1.33978 | New
MS-227 | PLANTA 2ª | MS-227 | 618.215 | 3350 | 1.95642 | New
MS-241 | PLANTA 2ª | MS-241 | 3862.5 | 3350 | 12.4801 | New
MS-241 | PLANTA 2ª | MS-241 | 2538.42 | 3350 | 8.08 | New
MS-241 | PLANTA 2ª | MS-241 | 800 | 3350 | 2.6384 | New
MS-241 | PLANTA 2ª | MS-241 | 2000.5 | 3350 | 6.59765 | New
MS-212 | PLANTA 2ª | MS-212 | 146.423 | 3350 | 0.288321 | New
MS-241 | PLANTA 2ª | MS-241 | 897.5 | 3350 | 2.95996 | New
MS-212 | PLANTA 2ª | MS-212 | 301 | 3350 | 0.910248 | New
MS-212 | PLANTA 2ª | MS-212 | 3522 | 3350 | 11.4877 | New
MS-228 | PLANTA 2ª | MS-228 | 439 | 3350 | 1.3207 | New

# IfcWallStandardCase: Pladur Tras 40 / 2N 66 (36)
Classification: 40.10.10.10 Envans (GuBIMclass CA); Material: Panel de Yeso Laminado 13 mm, Panel de Yeso Laminado 13 mm, ARQ_AI033_Aillament_Llana_De_Roca 40 mm
01-IDENTIFICADOR - 01-04-Tipus installacio: .; 01-05-Unitat de mesura: .
03-PRETACIONS - 03-01-Material: .; 03-02-RF: 0; 03-03-Pes-Kg: 0; 03-04-Potencia-W: 0; 03-05-Voltatge-V: 0; 03-06-Cabal -l/s: 0
02-LOCALIZACIÓ - 02-01-Nivell localització: .; 02-02-Codi ubicacio: .
05-MANTENIMENT - 05-01-Fabricant: .; 05-02-Marca: .; 05-03-Model: .; 05-06-Data installacio: aa/mm/dd; 05-07-Data inici garantia: aa/mm/dd; 05-08-Data final garantia: aa/mm/dd
06-ESPAIS - 06-01-Tipus us general: .; 06-01-Tipus us especific: .; 06-02-Numero: 0; 06-03-Nom: .; 06-04-Nivell: .; 06-03-Alçada lliure: 0; 06-06-Ocupació: 0; 06-05-Superficie: 0 m2
04-DIMENSIONS - 04-07-Volum-m3: 0; 04-08-Diametre-Exterior: 0; 04-09-Diametre-Interior: 0; 04-02-Amplada-m: 66 mm; 04-03-Alçada-m: 3350 mm; 04-04-Espesor-m: 66 mm; 04-06-Area-m2: 0 m2
07-PROPIETATS GENERALS - 07-01-Acabat: HPL
AC_Pset_RenovationAndPhasing - Renovation Status: New
Pset_WallCommon - IsExternal: no; LoadBearing: no
Name | In | 01-01-Nom tipus | 04-01-Longitud-m (mm) | 04-05-Perímetre-m (m2)
MS-212 | PLANTA 1ª | MS-212 | 252 | 0.7458
MS-212 | PLANTA 1ª | MS-212 | 252 | 0.733378
MS-212 | PLANTA 1ª | MS-212 | 466 | 1.51217
2 x MS-212 | PLANTA 1ª | MS-212 | 320 | 0.95403
2 x MS-212 | PLANTA 1ª | MS-212 | 580 | 1.8821
MS-212 | PLANTA 1ª | MS-212 | 1664.45 | 5.3038
2 x MS-212 | PLANTA 1ª | MS-212 | 332 | 0.99297
MS-212 | PLANTA 1ª | MS-212 | 5352 | 17.0348
MS-212 | PLANTA 1ª | MS-212 | 515 | 1.67221
MS-212 | PLANTA 1ª | MS-212 | 292 | 0.775857
MS-241 | PLANTA 1ª | MS-241 | 655.932 | 2.16326
MS-241 | PLANTA 1ª | MS-241 | 2089.92 | 6.8068
MS-241 | PLANTA 1ª | MS-241 | 2247.52 | 7.32658
MS-241 | PLANTA 1ª | MS-241 | 519.322 | 1.62698
MS-212 | PLANTA 2ª | MS-212 | 1443.21 | 4.59101
4 x MS-212 | PLANTA 2ª | MS-212 | 365 | 1.10006
MS-212 | PLANTA 2ª | MS-212 | 1620.45 | 5.17587
MS-212 | PLANTA 2ª | MS-212 | 568 | 1.87326
MS-212 | PLANTA 2ª | MS-212 | 319.215 | 0.878038
MS-212 | PLANTA 2ª | MS-212 | 569 | 1.82934
MS-212 | PLANTA 2ª | MS-212 | 4603.58 | 14.7892
MS-212 | PLANTA 2ª | MS-212 | 319.215 | 0.856986
MS-212 | PLANTA 2ª | MS-212 | 492 | 1.59654
MS-212 | PLANTA 2ª | MS-212 | 647 | 2.09951
MS-212 | PLANTA 2ª | MS-212 | 306.215 | 0.815191
MS-212 | PLANTA 2ª | MS-212 | 3035.53 | 9.75066
MS-212 | PLANTA 2ª | MS-212 | 666.42 | 2.11339
MS-241 | PLANTA 2ª | MS-241 | 519.322 | 0
MS-241 | PLANTA 2ª | MS-241 | 655.932 | 0.814375
MS-241 | PLANTA 2ª | MS-241 | 2342.57 | 7.72579

# IfcWallStandardCase: façana pati CR1 (ampit) 400 (3)
Classification: 40.10.10.10 Envans (GuBIMclass CA); Material: ARQ_AM246_Arrebossat_De_Guix 10 mm, ARQ_CE217_Gero 150 mm, ARQ_AI031_Aillament_Poliestireno expandido EPS 150 mm, ARQ_CE218_Ceramic 80 mm, ARQ_AM246_Arrebossat_De_Guix 10 mm
01-IDENTIFICADOR - 01-01-Nom tipus: MS-199; 01-04-Tipus installacio: .; 01-05-Unitat de mesura: .
02-LOCALIZACIÓ - 02-01-Nivell localització: .; 02-02-Codi ubicacio: .
03-PRETACIONS - 03-01-Material: .; 03-02-RF: 0; 03-03-Pes-Kg: 0; 03-04-Potencia-W: 0; 03-05-Voltatge-V: 0; 03-06-Cabal -l/s: 0
04-DIMENSIONS - 04-07-Volum-m3: 0; 04-08-Diametre-Exterior: 0; 04-09-Diametre-Interior: 0; 04-01-Longitud-m: 1200 mm; 04-02-Amplada-m: 400 mm; 04-03-Alçada-m: 3350 mm; 04-04-Espesor-m: 400 mm; 04-06-Area-m2: 0 m2
05-MANTENIMENT - 05-01-Fabricant: .; 05-02-Marca: .; 05-03-Model: .; 05-06-Data installacio: aa/mm/dd; 05-07-Data inici garantia: aa/mm/dd; 05-08-Data final garantia: aa/mm/dd
06-ESPAIS - 06-01-Tipus us general: .; 06-01-Tipus us especific: .; 06-02-Numero: 0; 06-03-Nom: .; 06-04-Nivell: .; 06-03-Alçada lliure: 0; 06-06-Ocupació: 0; 06-05-Superficie: 0 m2
07-PROPIETATS GENERALS - 07-01-Acabat: HPL
AC_Pset_RenovationAndPhasing - Renovation Status: Existing
Pset_WallCommon - IsExternal: no; LoadBearing: no
Name | In | 04-05-Perímetre-m (m2)
MS-199 | -1. Piso | 0.36
MS-199 | PLANTA 1ª | 0.42
MS-199 | PLANTA 2ª | 0.42

# IfcWallStandardCase: façana pati CR1 420 (6)
Classification: 40.10.10.10 Envans (GuBIMclass CA); Material: ARQ_CE217_Gero 150 mm, ARQ_AI031_Aillament_Poliestireno expandido EPS 180 mm, ARQ_CE218_Ceramic 80 mm, ARQ_AM246_Arrebossat_De_Guix 10 mm
01-IDENTIFICADOR - 01-01-Nom tipus: MS-200; 01-04-Tipus installacio: .; 01-05-Unitat de mesura: .
02-LOCALIZACIÓ - 02-01-Nivell localització: .; 02-02-Codi ubicacio: .
03-PRETACIONS - 03-01-Material: .; 03-02-RF: 0; 03-03-Pes-Kg: 0; 03-04-Potencia-W: 0; 03-05-Voltatge-V: 0; 03-06-Cabal -l/s: 0
04-DIMENSIONS - 04-07-Volum-m3: 0; 04-08-Diametre-Exterior: 0; 04-09-Diametre-Interior: 0; 04-02-Amplada-m: 420 mm; 04-03-Alçada-m: 3350 mm; 04-04-Espesor-m: 420 mm; 04-06-Area-m2: 0 m2
05-MANTENIMENT - 05-01-Fabricant: .; 05-02-Marca: .; 05-03-Model: .; 05-06-Data installacio: aa/mm/dd; 05-07-Data inici garantia: aa/mm/dd; 05-08-Data final garantia: aa/mm/dd
06-ESPAIS - 06-01-Tipus us general: .; 06-01-Tipus us especific: .; 06-02-Numero: 0; 06-03-Nom: .; 06-04-Nivell: .; 06-03-Alçada lliure: 0; 06-06-Ocupació: 0; 06-05-Superficie: 0 m2
07-PROPIETATS GENERALS - 07-01-Acabat: HPL
AC_Pset_RenovationAndPhasing - Renovation Status: Existing
Pset_WallCommon - IsExternal: no; LoadBearing: no
Name | In | 04-01-Longitud-m (mm) | 04-05-Perímetre-m (m2)
MS-200 | -1. Piso | 410 | 1.0385
MS-200 | -1. Piso | 9465 | 30.2393
MS-200 | PLANTA 1ª | 9465 | 30.2393
MS-200 | PLANTA 1ª | 410 | 1.0385
MS-200 | PLANTA 2ª | 410 | 1.0385
MS-200 | PLANTA 2ª | 9465 | 30.2393

# IfcWallStandardCase: façana pati CR2 (ampit) 480 (21)
Classification: 40.10.10.10 Envans (GuBIMclass CA); Material: ARQ_AM246_Arrebossat_De_Guix 10 mm, ARQ_CE217_Gero 120 mm, ARQ_AI031_Aillament_Poliestireno expandido EPS 120 mm, ARQ_CE218_Ceramic 220 mm, ARQ_AM246_Arrebossat_De_Guix 10 mm
01-IDENTIFICADOR - 01-01-Nom tipus: MS-200; 01-04-Tipus installacio: .; 01-05-Unitat de mesura: .
02-LOCALIZACIÓ - 02-01-Nivell localització: .; 02-02-Codi ubicacio: .
04-DIMENSIONS - 04-07-Volum-m3: 0; 04-08-Diametre-Exterior: 0; 04-09-Diametre-Interior: 0; 04-02-Amplada-m: 480 mm; 04-03-Alçada-m: 3350 mm; 04-04-Espesor-m: 480 mm; 04-06-Area-m2: 0 m2
05-MANTENIMENT - 05-01-Fabricant: .; 05-02-Marca: .; 05-03-Model: .; 05-06-Data installacio: aa/mm/dd; 05-07-Data inici garantia: aa/mm/dd; 05-08-Data final garantia: aa/mm/dd
03-PRETACIONS - 03-01-Material: .; 03-02-RF: 0; 03-03-Pes-Kg: 0; 03-04-Potencia-W: 0; 03-05-Voltatge-V: 0; 03-06-Cabal -l/s: 0
06-ESPAIS - 06-01-Tipus us general: .; 06-01-Tipus us especific: .; 06-02-Numero: 0; 06-03-Nom: .; 06-04-Nivell: .; 06-03-Alçada lliure: 0; 06-06-Ocupació: 0; 06-05-Superficie: 0 m2
AC_Pset_RenovationAndPhasing - Renovation Status: Existing
07-PROPIETATS GENERALS - 07-01-Acabat: HPL
Pset_WallCommon - IsExternal: no; LoadBearing: no
Name | In | 04-01-Longitud-m (mm) | 04-05-Perímetre-m (m2)
6 x MS-200 | -1. Piso | 1200 | 0.36
MS-200 | -1. Piso | 1282.32 | 0.631664
6 x MS-200 | PLANTA 1ª | 1200 | 0.42
MS-200 | PLANTA 1ª | 1282.32 | 0.69578
6 x MS-200 | PLANTA 2ª | 1200 | 0.42
MS-200 | PLANTA 2ª | 1282.32 | 0.69578

# IfcWallStandardCase: façana pati CR2 505 (21)
Classification: 40.10.10.10 Envans (GuBIMclass CA); Material: ARQ_CE217_Gero 10 mm, ARQ_CE217_Gero 90 mm, ARQ_AI031_Aillament_Poliestireno expandido EPS 180 mm, ARQ_CE218_Ceramic 215 mm, ARQ_AM246_Arrebossat_De_Guix 10 mm
01-IDENTIFICADOR - 01-01-Nom tipus: MS-200; 01-04-Tipus installacio: .; 01-05-Unitat de mesura: .
02-LOCALIZACIÓ - 02-01-Nivell localització: .; 02-02-Codi ubicacio: .
04-DIMENSIONS - 04-07-Volum-m3: 0; 04-08-Diametre-Exterior: 0; 04-09-Diametre-Interior: 0; 04-02-Amplada-m: 505 mm; 04-03-Alçada-m: 3350 mm; 04-04-Espesor-m: 505 mm; 04-06-Area-m2: 0 m2
03-PRETACIONS - 03-01-Material: .; 03-02-RF: 0; 03-03-Pes-Kg: 0; 03-04-Potencia-W: 0; 03-05-Voltatge-V: 0; 03-06-Cabal -l/s: 0
05-MANTENIMENT - 05-01-Fabricant: .; 05-02-Marca: .; 05-03-Model: .; 05-06-Data installacio: aa/mm/dd; 05-07-Data inici garantia: aa/mm/dd; 05-08-Data final garantia: aa/mm/dd
06-ESPAIS - 06-01-Tipus us general: .; 06-01-Tipus us especific: .; 06-02-Numero: 0; 06-03-Nom: .; 06-04-Nivell: .; 06-03-Alçada lliure: 0; 06-06-Ocupació: 0; 06-05-Superficie: 0 m2
07-PROPIETATS GENERALS - 07-01-Acabat: HPL
AC_Pset_RenovationAndPhasing - Renovation Status: Existing
Pset_WallCommon - IsExternal: no; LoadBearing: no
Name | In | 04-01-Longitud-m (mm) | 04-05-Perímetre-m (m2)
MS-200 | -1. Piso | 655.932 | 2.19737
MS-200 | -1. Piso | 897.5 | 3.00663
MS-200 | -1. Piso | 2342.57 | 7.8476
MS-200 | -1. Piso | 3932.5 | 13.1739
MS-200 | -1. Piso | 2684.42 | 7.7868
MS-200 | -1. Piso | 2800.5 | 9.38168
MS-200 | -1. Piso | 4154 | 13.9159
MS-200 | PLANTA 1ª | 4154 | 13.9159
MS-200 | PLANTA 1ª | 2800.5 | 9.38168
MS-200 | PLANTA 1ª | 2684.42 | 7.7868
MS-200 | PLANTA 1ª | 3932.5 | 13.1739
MS-200 | PLANTA 1ª | 655.932 | 2.19737
MS-200 | PLANTA 1ª | 897.5 | 3.00663
MS-200 | PLANTA 1ª | 2342.57 | 7.8476
MS-200 | PLANTA 2ª | 2342.57 | 7.8476
MS-200 | PLANTA 2ª | 897.5 | 3.00663
MS-200 | PLANTA 2ª | 655.932 | 2.19737
MS-200 | PLANTA 2ª | 3932.5 | 13.1739
MS-200 | PLANTA 2ª | 2684.42 | 7.7868
MS-200 | PLANTA 2ª | 2800.5 | 9.38168
MS-200 | PLANTA 2ª | 4154 | 13.9159

# IfcWallStandardCase: façana pati CR3 (ampit) 300 (24)
Classification: 40.10.10.10 Envans (GuBIMclass CA); Material: ARQ_AM246_Arrebossat_De_Guix 20 mm, ARQ_CE217_Gero 110 mm, ARQ_AI031_Aillament_Poliestireno expandido EPS 100 mm, ARQ_CE218_Ceramic 50 mm, ARQ_AM246_Arrebossat_De_Guix 20 mm
01-IDENTIFICADOR - 01-01-Nom tipus: MS-201; 01-04-Tipus installacio: .; 01-05-Unitat de mesura: .
02-LOCALIZACIÓ - 02-01-Nivell localització: .; 02-02-Codi ubicacio: .
03-PRETACIONS - 03-01-Material: .; 03-02-RF: 0; 03-03-Pes-Kg: 0; 03-04-Potencia-W: 0; 03-05-Voltatge-V: 0; 03-06-Cabal -l/s: 0
04-DIMENSIONS - 04-07-Volum-m3: 0; 04-08-Diametre-Exterior: 0; 04-09-Diametre-Interior: 0; 04-02-Amplada-m: 300 mm; 04-03-Alçada-m: 3350 mm; 04-04-Espesor-m: 300 mm; 04-06-Area-m2: 0 m2
05-MANTENIMENT - 05-01-Fabricant: .; 05-02-Marca: .; 05-03-Model: .; 05-06-Data installacio: aa/mm/dd; 05-07-Data inici garantia: aa/mm/dd; 05-08-Data final garantia: aa/mm/dd
06-ESPAIS - 06-01-Tipus us general: .; 06-01-Tipus us especific: .; 06-02-Numero: 0; 06-03-Nom: .; 06-04-Nivell: .; 06-03-Alçada lliure: 0; 06-06-Ocupació: 0; 06-05-Superficie: 0 m2
07-PROPIETATS GENERALS - 07-01-Acabat: HPL
AC_Pset_RenovationAndPhasing - Renovation Status: Existing
Pset_WallCommon - IsExternal: no; LoadBearing: no
Name | In | 04-01-Longitud-m (mm) | 04-05-Perímetre-m (m2)
MS-201 | -1. Piso | 1195 | 0.495686
6 x MS-201 | -1. Piso | 1195 | 0.3585
MS-201 | -1. Piso | 1350 | 0.359036
MS-201 | PLANTA 1ª | 1350 | 0.419036
4 x MS-201 | PLANTA 1ª | 1195 | 0.41825
MS-201 | PLANTA 1ª | 1200 | 0.42
MS-201 | PLANTA 1ª | 1295 | 0.405542
MS-201 | PLANTA 1ª | 1195 | 0.402245
6 x MS-201 | PLANTA 2ª | 1195 | 0.41825
MS-201 | PLANTA 2ª | 1195 | 0.555436
MS-201 | PLANTA 2ª | 1350 | 0.419036

# IfcWallStandardCase: façana pati CR3 320 (29)
Classification: 40.10.10.10 Envans (GuBIMclass CA); Material: ARQ_CE217_Gero 150 mm, ARQ_AI031_Aillament_Poliestireno expandido EPS 100 mm, ARQ_CE218_Ceramic 50 mm, ARQ_AM246_Arrebossat_De_Guix 20 mm
01-IDENTIFICADOR - 01-04-Tipus installacio: .; 01-05-Unitat de mesura: .
03-PRETACIONS - 03-01-Material: .; 03-02-RF: 0; 03-03-Pes-Kg: 0; 03-04-Potencia-W: 0; 03-05-Voltatge-V: 0; 03-06-Cabal -l/s: 0
04-DIMENSIONS - 04-07-Volum-m3: 0; 04-08-Diametre-Exterior: 0; 04-09-Diametre-Interior: 0; 04-02-Amplada-m: 320 mm; 04-04-Espesor-m: 320 mm; 04-06-Area-m2: 0 m2
05-MANTENIMENT - 05-01-Fabricant: .; 05-02-Marca: .; 05-03-Model: .; 05-06-Data installacio: aa/mm/dd; 05-07-Data inici garantia: aa/mm/dd; 05-08-Data final garantia: aa/mm/dd
06-ESPAIS - 06-01-Tipus us general: .; 06-01-Tipus us especific: .; 06-02-Numero: 0; 06-03-Nom: .; 06-04-Nivell: .; 06-03-Alçada lliure: 0; 06-06-Ocupació: 0; 06-05-Superficie: 0 m2
07-PROPIETATS GENERALS - 07-01-Acabat: HPL
AC_Pset_RenovationAndPhasing - Renovation Status: Existing
Pset_WallCommon - IsExternal: no; LoadBearing: no
02-LOCALIZACIÓ - 02-01-Nivell localització: .; 02-02-Codi ubicacio: .
Name | In | 01-01-Nom tipus | 04-01-Longitud-m (mm) | 04-03-Alçada-m (mm) | 04-05-Perímetre-m (m2)
MS-201 | -1. Piso | MS-201 | 3221.42 | 3350 | 10.7917
MS-201 | -1. Piso | MS-201 | 2540 | 3350 | 7.03131
MS-201 | -1. Piso | MS-201 | 3961.31 | 3350 | 13.2704
MS-201 | -1. Piso | MS-201 | 930 | 3350 | 3.1155
MS-201 | -1. Piso | MS-201 | 3355 | 3350 | 11.2393
MS-201 | -1. Piso | MS-201 | 425 | 3350 | 1.42375
MS-201 | -1. Piso | MS-201 | 1615 | 3350 | 5.41025
MS-201 | -1. Piso | MS-201 | 367.661 | 3350 | 0.432099
MS-201 | PLANTA 1ª | MS-201 | 367.661 | 3350 | 0.432099
MS-201 | PLANTA 1ª | MS-201 | 1610 | 3350 | 5.3935
MS-201 | PLANTA 1ª | MS-201 | 425 | 3350 | 1.42375
MS-201 | PLANTA 1ª | MS-201 | 3355 | 3350 | 11.2393
MS-201 | PLANTA 1ª | MS-201 | 2540 | 3350 | 7.03131
MS-201 | PLANTA 1ª | MS-201 | 3961.31 | 3350 | 13.2704
MS-201 | PLANTA 1ª | MS-201 | 930 | 3350 | 3.1155
MS-201 | PLANTA 1ª | MS-201 | 3221.42 | 3350 | 10.7917
MS-201 | PLANTA 2ª | MS-201 | 3221.42 | 3350 | 10.7917
MS-201 | PLANTA 2ª | MS-201 | 1615 | 3350 | 5.41025
MS-201 | PLANTA 2ª | MS-201 | 425 | 3350 | 1.42375
MS-201 | PLANTA 2ª | MS-201 | 367.661 | 3350 | 0.432099
MS-201 | PLANTA 2ª | MS-201 | 3961.31 | 3350 | 13.2704
MS-201 | PLANTA 2ª | MS-201 | 2540 | 3350 | 7.03131
MS-201 | PLANTA 2ª | MS-201 | 930 | 3350 | 3.1155
MS-201 | PLANTA 2ª | MS-201 | 3355 | 3350 | 11.2393
MS-201 | PLANTA 3 | MS-201 | 26249.7 | 1200 | 30.9357
MS-200 | PLANTA 3 | MS-200 | 10920 | 1200 | 12.384
MS-200 | PLANTA 3 | MS-200 | 26249.7 | 1200 | 30.9357
MS-200 | PLANTA 3 | MS-200 | 52850.3 | 1200 | 63.4204
MS-200 | PLANTA 3 | MS-200 | 10960 | 1200 | 12.744

# IfcWallStandardCase: façana pati CR4 (Ampit) 350 (3)
Classification: 40.10.10.10 Envans (GuBIMclass CA); Material: ARQ_AM246_Arrebossat_De_Guix 20 mm, ARQ_CE217_Gero 150 mm, ARQ_AI031_Aillament_Poliestireno expandido EPS 110 mm, ARQ_CE218_Ceramic 50 mm, ARQ_AM246_Arrebossat_De_Guix 20 mm
01-IDENTIFICADOR - 01-01-Nom tipus: MS-200; 01-04-Tipus installacio: .; 01-05-Unitat de mesura: .
02-LOCALIZACIÓ - 02-01-Nivell localització: .; 02-02-Codi ubicacio: .
03-PRETACIONS - 03-01-Material: .; 03-02-RF: 0; 03-03-Pes-Kg: 0; 03-04-Potencia-W: 0; 03-05-Voltatge-V: 0; 03-06-Cabal -l/s: 0
05-MANTENIMENT - 05-01-Fabricant: .; 05-02-Marca: .; 05-03-Model: .; 05-06-Data installacio: aa/mm/dd; 05-07-Data inici garantia: aa/mm/dd; 05-08-Data final garantia: aa/mm/dd
06-ESPAIS - 06-01-Tipus us general: .; 06-01-Tipus us especific: .; 06-02-Numero: 0; 06-03-Nom: .; 06-04-Nivell: .; 06-03-Alçada lliure: 0; 06-06-Ocupació: 0; 06-05-Superficie: 0 m2
07-PROPIETATS GENERALS - 07-01-Acabat: HPL
AC_Pset_RenovationAndPhasing - Renovation Status: Existing
Pset_WallCommon - IsExternal: no; LoadBearing: no
04-DIMENSIONS - 04-07-Volum-m3: 0; 04-08-Diametre-Exterior: 0; 04-09-Diametre-Interior: 0; 04-01-Longitud-m: 1186 mm; 04-02-Amplada-m: 350 mm; 04-03-Alçada-m: 3350 mm; 04-04-Espesor-m: 350 mm; 04-06-Area-m2: 0 m2
Name | In | 04-05-Perímetre-m (m2)
MS-200 | -1. Piso | 0.3558
MS-200 | PLANTA 1ª | 0.4151
MS-200 | PLANTA 2ª | 0.4151

# IfcWallStandardCase: façana pati CR4 360 (6)
Classification: 40.10.10.10 Envans (GuBIMclass CA); Material: ARQ_CE217_Gero 150 mm, ARQ_AI031_Aillament_Poliestireno expandido EPS 140 mm, ARQ_CE218_Ceramic 50 mm, ARQ_AM246_Arrebossat_De_Guix 20 mm
02-LOCALIZACIÓ - 02-01-Nivell localització: .; 02-02-Codi ubicacio: .
01-IDENTIFICADOR - 01-01-Nom tipus: MS-200; 01-04-Tipus installacio: .; 01-05-Unitat de mesura: .
03-PRETACIONS - 03-01-Material: .; 03-02-RF: 0; 03-03-Pes-Kg: 0; 03-04-Potencia-W: 0; 03-05-Voltatge-V: 0; 03-06-Cabal -l/s: 0
04-DIMENSIONS - 04-07-Volum-m3: 0; 04-08-Diametre-Exterior: 0; 04-09-Diametre-Interior: 0; 04-02-Amplada-m: 360 mm; 04-03-Alçada-m: 3350 mm; 04-04-Espesor-m: 360 mm; 04-06-Area-m2: 0 m2
06-ESPAIS - 06-01-Tipus us general: .; 06-01-Tipus us especific: .; 06-02-Numero: 0; 06-03-Nom: .; 06-04-Nivell: .; 06-03-Alçada lliure: 0; 06-06-Ocupació: 0; 06-05-Superficie: 0 m2
05-MANTENIMENT - 05-01-Fabricant: .; 05-02-Marca: .; 05-03-Model: .; 05-06-Data installacio: aa/mm/dd; 05-07-Data inici garantia: aa/mm/dd; 05-08-Data final garantia: aa/mm/dd
07-PROPIETATS GENERALS - 07-01-Acabat: HPL
Pset_WallCommon - IsExternal: no; LoadBearing: no
AC_Pset_RenovationAndPhasing - Renovation Status: Existing
Name | In | 04-01-Longitud-m (mm) | 04-05-Perímetre-m (m2)
MS-200 | -1. Piso | 868 | 2.9078
MS-200 | -1. Piso | 8276 | 27.7246
MS-200 | PLANTA 1ª | 8276 | 27.7246
MS-200 | PLANTA 1ª | 868 | 2.9078
MS-200 | PLANTA 2ª | 8276 | 27.7246
MS-200 | PLANTA 2ª | 868 | 2.9078

# IfcWallStandardCase: façana pati CR5 515 (3)
Classification: 40.10.10.10 Envans (GuBIMclass CA); Material: ARQ_CE217_Gero 100 mm, ARQ_AI031_Aillament_Poliestireno expandido EPS 205 mm, ARQ_CE218_Ceramic 200 mm, ARQ_AM246_Arrebossat_De_Guix 10 mm
01-IDENTIFICADOR - 01-01-Nom tipus: MS-201; 01-04-Tipus installacio: .; 01-05-Unitat de mesura: .
03-PRETACIONS - 03-01-Material: .; 03-02-RF: 0; 03-03-Pes-Kg: 0; 03-04-Potencia-W: 0; 03-05-Voltatge-V: 0; 03-06-Cabal -l/s: 0
02-LOCALIZACIÓ - 02-01-Nivell localització: .; 02-02-Codi ubicacio: .
04-DIMENSIONS - 04-07-Volum-m3: 0; 04-08-Diametre-Exterior: 0; 04-09-Diametre-Interior: 0; 04-02-Amplada-m: 515 mm; 04-03-Alçada-m: 3350 mm; 04-04-Espesor-m: 515 mm; 04-06-Area-m2: 0 m2
06-ESPAIS - 06-01-Tipus us general: .; 06-01-Tipus us especific: .; 06-02-Numero: 0; 06-03-Nom: .; 06-04-Nivell: .; 06-03-Alçada lliure: 0; 06-06-Ocupació: 0; 06-05-Superficie: 0 m2
07-PROPIETATS GENERALS - 07-01-Acabat: HPL
AC_Pset_RenovationAndPhasing - Renovation Status: Existing
Pset_WallCommon - IsExternal: no; LoadBearing: no
05-MANTENIMENT - 05-01-Fabricant: .; 05-02-Marca: .; 05-03-Model: .; 05-06-Data installacio: aa/mm/dd; 05-07-Data inici garantia: aa/mm/dd; 05-08-Data final garantia: aa/mm/dd
Name | In | 04-01-Longitud-m (mm) | 04-05-Perímetre-m (m2)
MS-201 | -1. Piso | 52850.3 | 166.489
MS-201 | PLANTA 1ª | 42162.7 | 121.205
MS-201 | PLANTA 2ª | 52850.3 | 157.009
